VERSION 5.8 ;
BUSBITCHARS "[]" ;
DIVIDERCHAR "/" ;
UNITS
    DATABASE MICRONS 1000 ;
END UNITS

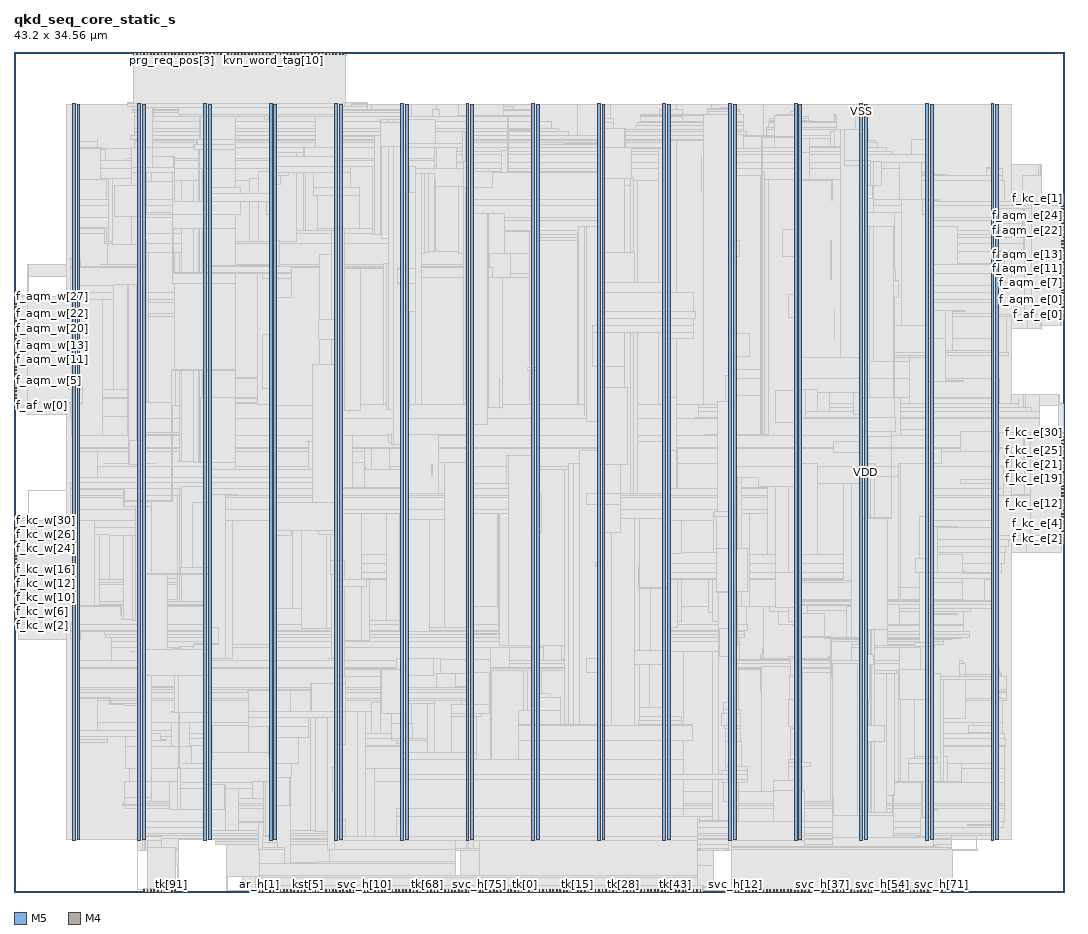
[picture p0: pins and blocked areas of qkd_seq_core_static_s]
MACRO qkd_seq_core_static_s
  FOREIGN qkd_seq_core_static_s 0 0 ;
  CLASS BLOCK ;
  SIZE 43.2 BY 34.56 ;
  PIN ar_h[0]
    DIRECTION INPUT ;
    USE SIGNAL ;
    PORT
      LAYER M5 ;
        RECT  9.936 0 9.96 0.084 ;
    END
  END ar_h[0]
  PIN ar_h[1]
    DIRECTION INPUT ;
    USE SIGNAL ;
    PORT
      LAYER M5 ;
        RECT  10.08 0 10.104 0.084 ;
    END
  END ar_h[1]
  PIN ar_h[2]
    DIRECTION INPUT ;
    USE SIGNAL ;
    PORT
      LAYER M5 ;
        RECT  10.224 0 10.248 0.084 ;
    END
  END ar_h[2]
  PIN ar_h[3]
    DIRECTION INPUT ;
    USE SIGNAL ;
    PORT
      LAYER M5 ;
        RECT  10.368 0 10.392 0.084 ;
    END
  END ar_h[3]
  PIN ar_h[4]
    DIRECTION INPUT ;
    USE SIGNAL ;
    PORT
      LAYER M5 ;
        RECT  10.512 0 10.536 0.084 ;
    END
  END ar_h[4]
  PIN ar_h[5]
    DIRECTION INPUT ;
    USE SIGNAL ;
    PORT
      LAYER M5 ;
        RECT  10.656 0 10.68 0.084 ;
    END
  END ar_h[5]
  PIN ar_h[6]
    DIRECTION INPUT ;
    USE SIGNAL ;
    PORT
      LAYER M5 ;
        RECT  10.8 0 10.824 0.084 ;
    END
  END ar_h[6]
  PIN ar_h[7]
    DIRECTION INPUT ;
    USE SIGNAL ;
    PORT
      LAYER M5 ;
        RECT  10.944 0 10.968 0.084 ;
    END
  END ar_h[7]
  PIN ck
    DIRECTION INPUT ;
    USE SIGNAL ;
    PORT
      LAYER M5 ;
        RECT  9.072 34.476 9.096 34.56 ;
    END
  END ck
  PIN f_af_e[0]
    DIRECTION INPUT ;
    USE SIGNAL ;
    PORT
      LAYER M4 ;
        RECT  43.116 23.76 43.2 23.784 ;
    END
  END f_af_e[0]
  PIN f_af_e[1]
    DIRECTION INPUT ;
    USE SIGNAL ;
    PORT
      LAYER M4 ;
        RECT  43.116 23.904 43.2 23.928 ;
    END
  END f_af_e[1]
  PIN f_af_w[0]
    DIRECTION INPUT ;
    USE SIGNAL ;
    PORT
      LAYER M4 ;
        RECT  0 20.016 0.084 20.04 ;
    END
  END f_af_w[0]
  PIN f_af_w[1]
    DIRECTION INPUT ;
    USE SIGNAL ;
    PORT
      LAYER M4 ;
        RECT  0 20.16 0.084 20.184 ;
    END
  END f_af_w[1]
  PIN f_aqm_e[0]
    DIRECTION OUTPUT ;
    USE SIGNAL ;
    PORT
      LAYER M4 ;
        RECT  43.116 24.048 43.2 24.072 ;
    END
  END f_aqm_e[0]
  PIN f_aqm_e[10]
    DIRECTION OUTPUT ;
    USE SIGNAL ;
    PORT
      LAYER M4 ;
        RECT  43.116 25.488 43.2 25.512 ;
    END
  END f_aqm_e[10]
  PIN f_aqm_e[11]
    DIRECTION OUTPUT ;
    USE SIGNAL ;
    PORT
      LAYER M4 ;
        RECT  43.116 25.632 43.2 25.656 ;
    END
  END f_aqm_e[11]
  PIN f_aqm_e[12]
    DIRECTION OUTPUT ;
    USE SIGNAL ;
    PORT
      LAYER M4 ;
        RECT  43.116 25.776 43.2 25.8 ;
    END
  END f_aqm_e[12]
  PIN f_aqm_e[13]
    DIRECTION OUTPUT ;
    USE SIGNAL ;
    PORT
      LAYER M4 ;
        RECT  43.116 25.92 43.2 25.944 ;
    END
  END f_aqm_e[13]
  PIN f_aqm_e[14]
    DIRECTION OUTPUT ;
    USE SIGNAL ;
    PORT
      LAYER M4 ;
        RECT  43.116 26.064 43.2 26.088 ;
    END
  END f_aqm_e[14]
  PIN f_aqm_e[15]
    DIRECTION OUTPUT ;
    USE SIGNAL ;
    PORT
      LAYER M4 ;
        RECT  43.116 26.208 43.2 26.232 ;
    END
  END f_aqm_e[15]
  PIN f_aqm_e[16]
    DIRECTION OUTPUT ;
    USE SIGNAL ;
    PORT
      LAYER M4 ;
        RECT  43.116 26.352 43.2 26.376 ;
    END
  END f_aqm_e[16]
  PIN f_aqm_e[17]
    DIRECTION OUTPUT ;
    USE SIGNAL ;
    PORT
      LAYER M4 ;
        RECT  43.116 26.496 43.2 26.52 ;
    END
  END f_aqm_e[17]
  PIN f_aqm_e[18]
    DIRECTION OUTPUT ;
    USE SIGNAL ;
    PORT
      LAYER M4 ;
        RECT  43.116 26.64 43.2 26.664 ;
    END
  END f_aqm_e[18]
  PIN f_aqm_e[19]
    DIRECTION OUTPUT ;
    USE SIGNAL ;
    PORT
      LAYER M4 ;
        RECT  43.116 26.784 43.2 26.808 ;
    END
  END f_aqm_e[19]
  PIN f_aqm_e[1]
    DIRECTION OUTPUT ;
    USE SIGNAL ;
    PORT
      LAYER M4 ;
        RECT  43.116 24.192 43.2 24.216 ;
    END
  END f_aqm_e[1]
  PIN f_aqm_e[20]
    DIRECTION OUTPUT ;
    USE SIGNAL ;
    PORT
      LAYER M4 ;
        RECT  43.116 26.928 43.2 26.952 ;
    END
  END f_aqm_e[20]
  PIN f_aqm_e[21]
    DIRECTION OUTPUT ;
    USE SIGNAL ;
    PORT
      LAYER M4 ;
        RECT  43.116 27.072 43.2 27.096 ;
    END
  END f_aqm_e[21]
  PIN f_aqm_e[22]
    DIRECTION OUTPUT ;
    USE SIGNAL ;
    PORT
      LAYER M4 ;
        RECT  43.116 27.216 43.2 27.24 ;
    END
  END f_aqm_e[22]
  PIN f_aqm_e[23]
    DIRECTION OUTPUT ;
    USE SIGNAL ;
    PORT
      LAYER M4 ;
        RECT  43.116 27.36 43.2 27.384 ;
    END
  END f_aqm_e[23]
  PIN f_aqm_e[24]
    DIRECTION OUTPUT ;
    USE SIGNAL ;
    PORT
      LAYER M4 ;
        RECT  43.116 27.504 43.2 27.528 ;
    END
  END f_aqm_e[24]
  PIN f_aqm_e[25]
    DIRECTION OUTPUT ;
    USE SIGNAL ;
    PORT
      LAYER M4 ;
        RECT  43.116 27.648 43.2 27.672 ;
    END
  END f_aqm_e[25]
  PIN f_aqm_e[26]
    DIRECTION OUTPUT ;
    USE SIGNAL ;
    PORT
      LAYER M4 ;
        RECT  43.116 27.792 43.2 27.816 ;
    END
  END f_aqm_e[26]
  PIN f_aqm_e[27]
    DIRECTION OUTPUT ;
    USE SIGNAL ;
    PORT
      LAYER M4 ;
        RECT  43.116 27.936 43.2 27.96 ;
    END
  END f_aqm_e[27]
  PIN f_aqm_e[2]
    DIRECTION OUTPUT ;
    USE SIGNAL ;
    PORT
      LAYER M4 ;
        RECT  43.116 24.336 43.2 24.36 ;
    END
  END f_aqm_e[2]
  PIN f_aqm_e[3]
    DIRECTION OUTPUT ;
    USE SIGNAL ;
    PORT
      LAYER M4 ;
        RECT  43.116 24.48 43.2 24.504 ;
    END
  END f_aqm_e[3]
  PIN f_aqm_e[4]
    DIRECTION OUTPUT ;
    USE SIGNAL ;
    PORT
      LAYER M4 ;
        RECT  43.116 24.624 43.2 24.648 ;
    END
  END f_aqm_e[4]
  PIN f_aqm_e[5]
    DIRECTION OUTPUT ;
    USE SIGNAL ;
    PORT
      LAYER M4 ;
        RECT  43.116 24.768 43.2 24.792 ;
    END
  END f_aqm_e[5]
  PIN f_aqm_e[6]
    DIRECTION OUTPUT ;
    USE SIGNAL ;
    PORT
      LAYER M4 ;
        RECT  43.116 24.912 43.2 24.936 ;
    END
  END f_aqm_e[6]
  PIN f_aqm_e[7]
    DIRECTION OUTPUT ;
    USE SIGNAL ;
    PORT
      LAYER M4 ;
        RECT  43.116 25.056 43.2 25.08 ;
    END
  END f_aqm_e[7]
  PIN f_aqm_e[8]
    DIRECTION OUTPUT ;
    USE SIGNAL ;
    PORT
      LAYER M4 ;
        RECT  43.116 25.2 43.2 25.224 ;
    END
  END f_aqm_e[8]
  PIN f_aqm_e[9]
    DIRECTION OUTPUT ;
    USE SIGNAL ;
    PORT
      LAYER M4 ;
        RECT  43.116 25.344 43.2 25.368 ;
    END
  END f_aqm_e[9]
  PIN f_aqm_w[0]
    DIRECTION OUTPUT ;
    USE SIGNAL ;
    PORT
      LAYER M4 ;
        RECT  0 20.304 0.084 20.328 ;
    END
  END f_aqm_w[0]
  PIN f_aqm_w[10]
    DIRECTION OUTPUT ;
    USE SIGNAL ;
    PORT
      LAYER M4 ;
        RECT  0 21.744 0.084 21.768 ;
    END
  END f_aqm_w[10]
  PIN f_aqm_w[11]
    DIRECTION OUTPUT ;
    USE SIGNAL ;
    PORT
      LAYER M4 ;
        RECT  0 21.888 0.084 21.912 ;
    END
  END f_aqm_w[11]
  PIN f_aqm_w[12]
    DIRECTION OUTPUT ;
    USE SIGNAL ;
    PORT
      LAYER M4 ;
        RECT  0 22.032 0.084 22.056 ;
    END
  END f_aqm_w[12]
  PIN f_aqm_w[13]
    DIRECTION OUTPUT ;
    USE SIGNAL ;
    PORT
      LAYER M4 ;
        RECT  0 22.176 0.084 22.2 ;
    END
  END f_aqm_w[13]
  PIN f_aqm_w[14]
    DIRECTION OUTPUT ;
    USE SIGNAL ;
    PORT
      LAYER M4 ;
        RECT  0 22.32 0.084 22.344 ;
    END
  END f_aqm_w[14]
  PIN f_aqm_w[15]
    DIRECTION OUTPUT ;
    USE SIGNAL ;
    PORT
      LAYER M4 ;
        RECT  0 22.464 0.084 22.488 ;
    END
  END f_aqm_w[15]
  PIN f_aqm_w[16]
    DIRECTION OUTPUT ;
    USE SIGNAL ;
    PORT
      LAYER M4 ;
        RECT  0 22.608 0.084 22.632 ;
    END
  END f_aqm_w[16]
  PIN f_aqm_w[17]
    DIRECTION OUTPUT ;
    USE SIGNAL ;
    PORT
      LAYER M4 ;
        RECT  0 22.752 0.084 22.776 ;
    END
  END f_aqm_w[17]
  PIN f_aqm_w[18]
    DIRECTION OUTPUT ;
    USE SIGNAL ;
    PORT
      LAYER M4 ;
        RECT  0 22.896 0.084 22.92 ;
    END
  END f_aqm_w[18]
  PIN f_aqm_w[19]
    DIRECTION OUTPUT ;
    USE SIGNAL ;
    PORT
      LAYER M4 ;
        RECT  0 23.04 0.084 23.064 ;
    END
  END f_aqm_w[19]
  PIN f_aqm_w[1]
    DIRECTION OUTPUT ;
    USE SIGNAL ;
    PORT
      LAYER M4 ;
        RECT  0 20.448 0.084 20.472 ;
    END
  END f_aqm_w[1]
  PIN f_aqm_w[20]
    DIRECTION OUTPUT ;
    USE SIGNAL ;
    PORT
      LAYER M4 ;
        RECT  0 23.184 0.084 23.208 ;
    END
  END f_aqm_w[20]
  PIN f_aqm_w[21]
    DIRECTION OUTPUT ;
    USE SIGNAL ;
    PORT
      LAYER M4 ;
        RECT  0 23.328 0.084 23.352 ;
    END
  END f_aqm_w[21]
  PIN f_aqm_w[22]
    DIRECTION OUTPUT ;
    USE SIGNAL ;
    PORT
      LAYER M4 ;
        RECT  0 23.472 0.084 23.496 ;
    END
  END f_aqm_w[22]
  PIN f_aqm_w[23]
    DIRECTION OUTPUT ;
    USE SIGNAL ;
    PORT
      LAYER M4 ;
        RECT  0 23.616 0.084 23.64 ;
    END
  END f_aqm_w[23]
  PIN f_aqm_w[24]
    DIRECTION OUTPUT ;
    USE SIGNAL ;
    PORT
      LAYER M4 ;
        RECT  0 23.76 0.084 23.784 ;
    END
  END f_aqm_w[24]
  PIN f_aqm_w[25]
    DIRECTION OUTPUT ;
    USE SIGNAL ;
    PORT
      LAYER M4 ;
        RECT  0 23.904 0.084 23.928 ;
    END
  END f_aqm_w[25]
  PIN f_aqm_w[26]
    DIRECTION OUTPUT ;
    USE SIGNAL ;
    PORT
      LAYER M4 ;
        RECT  0 24.048 0.084 24.072 ;
    END
  END f_aqm_w[26]
  PIN f_aqm_w[27]
    DIRECTION OUTPUT ;
    USE SIGNAL ;
    PORT
      LAYER M4 ;
        RECT  0 24.192 0.084 24.216 ;
    END
  END f_aqm_w[27]
  PIN f_aqm_w[2]
    DIRECTION OUTPUT ;
    USE SIGNAL ;
    PORT
      LAYER M4 ;
        RECT  0 20.592 0.084 20.616 ;
    END
  END f_aqm_w[2]
  PIN f_aqm_w[3]
    DIRECTION OUTPUT ;
    USE SIGNAL ;
    PORT
      LAYER M4 ;
        RECT  0 20.736 0.084 20.76 ;
    END
  END f_aqm_w[3]
  PIN f_aqm_w[4]
    DIRECTION OUTPUT ;
    USE SIGNAL ;
    PORT
      LAYER M4 ;
        RECT  0 20.88 0.084 20.904 ;
    END
  END f_aqm_w[4]
  PIN f_aqm_w[5]
    DIRECTION OUTPUT ;
    USE SIGNAL ;
    PORT
      LAYER M4 ;
        RECT  0 21.024 0.084 21.048 ;
    END
  END f_aqm_w[5]
  PIN f_aqm_w[6]
    DIRECTION OUTPUT ;
    USE SIGNAL ;
    PORT
      LAYER M4 ;
        RECT  0 21.168 0.084 21.192 ;
    END
  END f_aqm_w[6]
  PIN f_aqm_w[7]
    DIRECTION OUTPUT ;
    USE SIGNAL ;
    PORT
      LAYER M4 ;
        RECT  0 21.312 0.084 21.336 ;
    END
  END f_aqm_w[7]
  PIN f_aqm_w[8]
    DIRECTION OUTPUT ;
    USE SIGNAL ;
    PORT
      LAYER M4 ;
        RECT  0 21.456 0.084 21.48 ;
    END
  END f_aqm_w[8]
  PIN f_aqm_w[9]
    DIRECTION OUTPUT ;
    USE SIGNAL ;
    PORT
      LAYER M4 ;
        RECT  0 21.6 0.084 21.624 ;
    END
  END f_aqm_w[9]
  PIN f_kc_e[0]
    DIRECTION OUTPUT ;
    USE SIGNAL ;
    PORT
      LAYER M4 ;
        RECT  43.116 28.08 43.2 28.104 ;
    END
  END f_kc_e[0]
  PIN f_kc_e[10]
    DIRECTION OUTPUT ;
    USE SIGNAL ;
    PORT
      LAYER M4 ;
        RECT  43.116 15.696 43.2 15.72 ;
    END
  END f_kc_e[10]
  PIN f_kc_e[11]
    DIRECTION OUTPUT ;
    USE SIGNAL ;
    PORT
      LAYER M4 ;
        RECT  43.116 15.84 43.2 15.864 ;
    END
  END f_kc_e[11]
  PIN f_kc_e[12]
    DIRECTION OUTPUT ;
    USE SIGNAL ;
    PORT
      LAYER M4 ;
        RECT  43.116 15.984 43.2 16.008 ;
    END
  END f_kc_e[12]
  PIN f_kc_e[13]
    DIRECTION OUTPUT ;
    USE SIGNAL ;
    PORT
      LAYER M4 ;
        RECT  43.116 16.128 43.2 16.152 ;
    END
  END f_kc_e[13]
  PIN f_kc_e[14]
    DIRECTION OUTPUT ;
    USE SIGNAL ;
    PORT
      LAYER M4 ;
        RECT  43.116 16.272 43.2 16.296 ;
    END
  END f_kc_e[14]
  PIN f_kc_e[15]
    DIRECTION OUTPUT ;
    USE SIGNAL ;
    PORT
      LAYER M4 ;
        RECT  43.116 16.416 43.2 16.44 ;
    END
  END f_kc_e[15]
  PIN f_kc_e[16]
    DIRECTION OUTPUT ;
    USE SIGNAL ;
    PORT
      LAYER M4 ;
        RECT  43.116 16.56 43.2 16.584 ;
    END
  END f_kc_e[16]
  PIN f_kc_e[17]
    DIRECTION OUTPUT ;
    USE SIGNAL ;
    PORT
      LAYER M4 ;
        RECT  43.116 16.704 43.2 16.728 ;
    END
  END f_kc_e[17]
  PIN f_kc_e[18]
    DIRECTION OUTPUT ;
    USE SIGNAL ;
    PORT
      LAYER M4 ;
        RECT  43.116 16.848 43.2 16.872 ;
    END
  END f_kc_e[18]
  PIN f_kc_e[19]
    DIRECTION OUTPUT ;
    USE SIGNAL ;
    PORT
      LAYER M4 ;
        RECT  43.116 16.992 43.2 17.016 ;
    END
  END f_kc_e[19]
  PIN f_kc_e[1]
    DIRECTION OUTPUT ;
    USE SIGNAL ;
    PORT
      LAYER M4 ;
        RECT  43.116 28.224 43.2 28.248 ;
    END
  END f_kc_e[1]
  PIN f_kc_e[20]
    DIRECTION OUTPUT ;
    USE SIGNAL ;
    PORT
      LAYER M4 ;
        RECT  43.116 17.136 43.2 17.16 ;
    END
  END f_kc_e[20]
  PIN f_kc_e[21]
    DIRECTION OUTPUT ;
    USE SIGNAL ;
    PORT
      LAYER M4 ;
        RECT  43.116 17.28 43.2 17.304 ;
    END
  END f_kc_e[21]
  PIN f_kc_e[22]
    DIRECTION OUTPUT ;
    USE SIGNAL ;
    PORT
      LAYER M4 ;
        RECT  43.116 17.424 43.2 17.448 ;
    END
  END f_kc_e[22]
  PIN f_kc_e[23]
    DIRECTION OUTPUT ;
    USE SIGNAL ;
    PORT
      LAYER M4 ;
        RECT  43.116 17.568 43.2 17.592 ;
    END
  END f_kc_e[23]
  PIN f_kc_e[24]
    DIRECTION OUTPUT ;
    USE SIGNAL ;
    PORT
      LAYER M4 ;
        RECT  43.116 17.712 43.2 17.736 ;
    END
  END f_kc_e[24]
  PIN f_kc_e[25]
    DIRECTION OUTPUT ;
    USE SIGNAL ;
    PORT
      LAYER M4 ;
        RECT  43.116 17.856 43.2 17.88 ;
    END
  END f_kc_e[25]
  PIN f_kc_e[26]
    DIRECTION OUTPUT ;
    USE SIGNAL ;
    PORT
      LAYER M4 ;
        RECT  43.116 18 43.2 18.024 ;
    END
  END f_kc_e[26]
  PIN f_kc_e[27]
    DIRECTION OUTPUT ;
    USE SIGNAL ;
    PORT
      LAYER M4 ;
        RECT  43.116 18.144 43.2 18.168 ;
    END
  END f_kc_e[27]
  PIN f_kc_e[28]
    DIRECTION OUTPUT ;
    USE SIGNAL ;
    PORT
      LAYER M4 ;
        RECT  43.116 18.288 43.2 18.312 ;
    END
  END f_kc_e[28]
  PIN f_kc_e[29]
    DIRECTION OUTPUT ;
    USE SIGNAL ;
    PORT
      LAYER M4 ;
        RECT  43.116 18.432 43.2 18.456 ;
    END
  END f_kc_e[29]
  PIN f_kc_e[2]
    DIRECTION OUTPUT ;
    USE SIGNAL ;
    PORT
      LAYER M4 ;
        RECT  43.116 14.544 43.2 14.568 ;
    END
  END f_kc_e[2]
  PIN f_kc_e[30]
    DIRECTION OUTPUT ;
    USE SIGNAL ;
    PORT
      LAYER M4 ;
        RECT  43.116 18.576 43.2 18.6 ;
    END
  END f_kc_e[30]
  PIN f_kc_e[31]
    DIRECTION OUTPUT ;
    USE SIGNAL ;
    PORT
      LAYER M4 ;
        RECT  43.116 18.72 43.2 18.744 ;
    END
  END f_kc_e[31]
  PIN f_kc_e[32]
    DIRECTION OUTPUT ;
    USE SIGNAL ;
    PORT
      LAYER M4 ;
        RECT  43.116 18.864 43.2 18.888 ;
    END
  END f_kc_e[32]
  PIN f_kc_e[3]
    DIRECTION OUTPUT ;
    USE SIGNAL ;
    PORT
      LAYER M4 ;
        RECT  43.116 14.688 43.2 14.712 ;
    END
  END f_kc_e[3]
  PIN f_kc_e[4]
    DIRECTION OUTPUT ;
    USE SIGNAL ;
    PORT
      LAYER M4 ;
        RECT  43.116 14.832 43.2 14.856 ;
    END
  END f_kc_e[4]
  PIN f_kc_e[5]
    DIRECTION OUTPUT ;
    USE SIGNAL ;
    PORT
      LAYER M4 ;
        RECT  43.116 14.976 43.2 15 ;
    END
  END f_kc_e[5]
  PIN f_kc_e[6]
    DIRECTION OUTPUT ;
    USE SIGNAL ;
    PORT
      LAYER M4 ;
        RECT  43.116 15.12 43.2 15.144 ;
    END
  END f_kc_e[6]
  PIN f_kc_e[7]
    DIRECTION OUTPUT ;
    USE SIGNAL ;
    PORT
      LAYER M4 ;
        RECT  43.116 15.264 43.2 15.288 ;
    END
  END f_kc_e[7]
  PIN f_kc_e[8]
    DIRECTION OUTPUT ;
    USE SIGNAL ;
    PORT
      LAYER M4 ;
        RECT  43.116 15.408 43.2 15.432 ;
    END
  END f_kc_e[8]
  PIN f_kc_e[9]
    DIRECTION OUTPUT ;
    USE SIGNAL ;
    PORT
      LAYER M4 ;
        RECT  43.116 15.552 43.2 15.576 ;
    END
  END f_kc_e[9]
  PIN f_kc_w[0]
    DIRECTION OUTPUT ;
    USE SIGNAL ;
    PORT
      LAYER M4 ;
        RECT  0 24.336 0.084 24.36 ;
    END
  END f_kc_w[0]
  PIN f_kc_w[10]
    DIRECTION OUTPUT ;
    USE SIGNAL ;
    PORT
      LAYER M4 ;
        RECT  0 12.096 0.084 12.12 ;
    END
  END f_kc_w[10]
  PIN f_kc_w[11]
    DIRECTION OUTPUT ;
    USE SIGNAL ;
    PORT
      LAYER M4 ;
        RECT  0 12.24 0.084 12.264 ;
    END
  END f_kc_w[11]
  PIN f_kc_w[12]
    DIRECTION OUTPUT ;
    USE SIGNAL ;
    PORT
      LAYER M4 ;
        RECT  0 12.384 0.084 12.408 ;
    END
  END f_kc_w[12]
  PIN f_kc_w[13]
    DIRECTION OUTPUT ;
    USE SIGNAL ;
    PORT
      LAYER M4 ;
        RECT  0 12.528 0.084 12.552 ;
    END
  END f_kc_w[13]
  PIN f_kc_w[14]
    DIRECTION OUTPUT ;
    USE SIGNAL ;
    PORT
      LAYER M4 ;
        RECT  0 12.672 0.084 12.696 ;
    END
  END f_kc_w[14]
  PIN f_kc_w[15]
    DIRECTION OUTPUT ;
    USE SIGNAL ;
    PORT
      LAYER M4 ;
        RECT  0 12.816 0.084 12.84 ;
    END
  END f_kc_w[15]
  PIN f_kc_w[16]
    DIRECTION OUTPUT ;
    USE SIGNAL ;
    PORT
      LAYER M4 ;
        RECT  0 12.96 0.084 12.984 ;
    END
  END f_kc_w[16]
  PIN f_kc_w[17]
    DIRECTION OUTPUT ;
    USE SIGNAL ;
    PORT
      LAYER M4 ;
        RECT  0 13.104 0.084 13.128 ;
    END
  END f_kc_w[17]
  PIN f_kc_w[18]
    DIRECTION OUTPUT ;
    USE SIGNAL ;
    PORT
      LAYER M4 ;
        RECT  0 13.248 0.084 13.272 ;
    END
  END f_kc_w[18]
  PIN f_kc_w[19]
    DIRECTION OUTPUT ;
    USE SIGNAL ;
    PORT
      LAYER M4 ;
        RECT  0 13.392 0.084 13.416 ;
    END
  END f_kc_w[19]
  PIN f_kc_w[1]
    DIRECTION OUTPUT ;
    USE SIGNAL ;
    PORT
      LAYER M4 ;
        RECT  0 24.48 0.084 24.504 ;
    END
  END f_kc_w[1]
  PIN f_kc_w[20]
    DIRECTION OUTPUT ;
    USE SIGNAL ;
    PORT
      LAYER M4 ;
        RECT  0 13.536 0.084 13.56 ;
    END
  END f_kc_w[20]
  PIN f_kc_w[21]
    DIRECTION OUTPUT ;
    USE SIGNAL ;
    PORT
      LAYER M4 ;
        RECT  0 13.68 0.084 13.704 ;
    END
  END f_kc_w[21]
  PIN f_kc_w[22]
    DIRECTION OUTPUT ;
    USE SIGNAL ;
    PORT
      LAYER M4 ;
        RECT  0 13.824 0.084 13.848 ;
    END
  END f_kc_w[22]
  PIN f_kc_w[23]
    DIRECTION OUTPUT ;
    USE SIGNAL ;
    PORT
      LAYER M4 ;
        RECT  0 13.968 0.084 13.992 ;
    END
  END f_kc_w[23]
  PIN f_kc_w[24]
    DIRECTION OUTPUT ;
    USE SIGNAL ;
    PORT
      LAYER M4 ;
        RECT  0 14.112 0.084 14.136 ;
    END
  END f_kc_w[24]
  PIN f_kc_w[25]
    DIRECTION OUTPUT ;
    USE SIGNAL ;
    PORT
      LAYER M4 ;
        RECT  0 14.256 0.084 14.28 ;
    END
  END f_kc_w[25]
  PIN f_kc_w[26]
    DIRECTION OUTPUT ;
    USE SIGNAL ;
    PORT
      LAYER M4 ;
        RECT  0 14.4 0.084 14.424 ;
    END
  END f_kc_w[26]
  PIN f_kc_w[27]
    DIRECTION OUTPUT ;
    USE SIGNAL ;
    PORT
      LAYER M4 ;
        RECT  0 14.544 0.084 14.568 ;
    END
  END f_kc_w[27]
  PIN f_kc_w[28]
    DIRECTION OUTPUT ;
    USE SIGNAL ;
    PORT
      LAYER M4 ;
        RECT  0 14.688 0.084 14.712 ;
    END
  END f_kc_w[28]
  PIN f_kc_w[29]
    DIRECTION OUTPUT ;
    USE SIGNAL ;
    PORT
      LAYER M4 ;
        RECT  0 14.832 0.084 14.856 ;
    END
  END f_kc_w[29]
  PIN f_kc_w[2]
    DIRECTION OUTPUT ;
    USE SIGNAL ;
    PORT
      LAYER M4 ;
        RECT  0 10.944 0.084 10.968 ;
    END
  END f_kc_w[2]
  PIN f_kc_w[30]
    DIRECTION OUTPUT ;
    USE SIGNAL ;
    PORT
      LAYER M4 ;
        RECT  0 14.976 0.084 15 ;
    END
  END f_kc_w[30]
  PIN f_kc_w[31]
    DIRECTION OUTPUT ;
    USE SIGNAL ;
    PORT
      LAYER M4 ;
        RECT  0 15.12 0.084 15.144 ;
    END
  END f_kc_w[31]
  PIN f_kc_w[32]
    DIRECTION OUTPUT ;
    USE SIGNAL ;
    PORT
      LAYER M4 ;
        RECT  0 15.264 0.084 15.288 ;
    END
  END f_kc_w[32]
  PIN f_kc_w[3]
    DIRECTION OUTPUT ;
    USE SIGNAL ;
    PORT
      LAYER M4 ;
        RECT  0 11.088 0.084 11.112 ;
    END
  END f_kc_w[3]
  PIN f_kc_w[4]
    DIRECTION OUTPUT ;
    USE SIGNAL ;
    PORT
      LAYER M4 ;
        RECT  0 11.232 0.084 11.256 ;
    END
  END f_kc_w[4]
  PIN f_kc_w[5]
    DIRECTION OUTPUT ;
    USE SIGNAL ;
    PORT
      LAYER M4 ;
        RECT  0 11.376 0.084 11.4 ;
    END
  END f_kc_w[5]
  PIN f_kc_w[6]
    DIRECTION OUTPUT ;
    USE SIGNAL ;
    PORT
      LAYER M4 ;
        RECT  0 11.52 0.084 11.544 ;
    END
  END f_kc_w[6]
  PIN f_kc_w[7]
    DIRECTION OUTPUT ;
    USE SIGNAL ;
    PORT
      LAYER M4 ;
        RECT  0 11.664 0.084 11.688 ;
    END
  END f_kc_w[7]
  PIN f_kc_w[8]
    DIRECTION OUTPUT ;
    USE SIGNAL ;
    PORT
      LAYER M4 ;
        RECT  0 11.808 0.084 11.832 ;
    END
  END f_kc_w[8]
  PIN f_kc_w[9]
    DIRECTION OUTPUT ;
    USE SIGNAL ;
    PORT
      LAYER M4 ;
        RECT  0 11.952 0.084 11.976 ;
    END
  END f_kc_w[9]
  PIN hf
    DIRECTION INPUT ;
    USE SIGNAL ;
    PORT
      LAYER M5 ;
        RECT  11.088 0 11.112 0.084 ;
    END
  END hf
  PIN hs
    DIRECTION OUTPUT ;
    USE SIGNAL ;
    PORT
      LAYER M5 ;
        RECT  11.232 0 11.256 0.084 ;
    END
  END hs
  PIN kst[0]
    DIRECTION OUTPUT ;
    USE SIGNAL ;
    PORT
      LAYER M5 ;
        RECT  11.376 0 11.4 0.084 ;
    END
  END kst[0]
  PIN kst[1]
    DIRECTION OUTPUT ;
    USE SIGNAL ;
    PORT
      LAYER M5 ;
        RECT  11.52 0 11.544 0.084 ;
    END
  END kst[1]
  PIN kst[2]
    DIRECTION OUTPUT ;
    USE SIGNAL ;
    PORT
      LAYER M5 ;
        RECT  11.664 0 11.688 0.084 ;
    END
  END kst[2]
  PIN kst[3]
    DIRECTION OUTPUT ;
    USE SIGNAL ;
    PORT
      LAYER M5 ;
        RECT  11.808 0 11.832 0.084 ;
    END
  END kst[3]
  PIN kst[4]
    DIRECTION OUTPUT ;
    USE SIGNAL ;
    PORT
      LAYER M5 ;
        RECT  11.952 0 11.976 0.084 ;
    END
  END kst[4]
  PIN kst[5]
    DIRECTION OUTPUT ;
    USE SIGNAL ;
    PORT
      LAYER M5 ;
        RECT  12.096 0 12.12 0.084 ;
    END
  END kst[5]
  PIN kst[6]
    DIRECTION OUTPUT ;
    USE SIGNAL ;
    PORT
      LAYER M5 ;
        RECT  12.24 0 12.264 0.084 ;
    END
  END kst[6]
  PIN kst[7]
    DIRECTION OUTPUT ;
    USE SIGNAL ;
    PORT
      LAYER M5 ;
        RECT  12.384 0 12.408 0.084 ;
    END
  END kst[7]
  PIN kst[8]
    DIRECTION OUTPUT ;
    USE SIGNAL ;
    PORT
      LAYER M5 ;
        RECT  12.528 0 12.552 0.084 ;
    END
  END kst[8]
  PIN kst[9]
    DIRECTION OUTPUT ;
    USE SIGNAL ;
    PORT
      LAYER M5 ;
        RECT  12.672 0 12.696 0.084 ;
    END
  END kst[9]
  PIN kvn_word_tag[0]
    DIRECTION INPUT ;
    USE SIGNAL ;
    PORT
      LAYER M5 ;
        RECT  9.216 34.476 9.24 34.56 ;
    END
  END kvn_word_tag[0]
  PIN kvn_word_tag[10]
    DIRECTION INPUT ;
    USE SIGNAL ;
    PORT
      LAYER M5 ;
        RECT  10.656 34.476 10.68 34.56 ;
    END
  END kvn_word_tag[10]
  PIN kvn_word_tag[1]
    DIRECTION INPUT ;
    USE SIGNAL ;
    PORT
      LAYER M5 ;
        RECT  9.36 34.476 9.384 34.56 ;
    END
  END kvn_word_tag[1]
  PIN kvn_word_tag[2]
    DIRECTION INPUT ;
    USE SIGNAL ;
    PORT
      LAYER M5 ;
        RECT  9.504 34.476 9.528 34.56 ;
    END
  END kvn_word_tag[2]
  PIN kvn_word_tag[3]
    DIRECTION INPUT ;
    USE SIGNAL ;
    PORT
      LAYER M5 ;
        RECT  9.648 34.476 9.672 34.56 ;
    END
  END kvn_word_tag[3]
  PIN kvn_word_tag[4]
    DIRECTION INPUT ;
    USE SIGNAL ;
    PORT
      LAYER M5 ;
        RECT  9.792 34.476 9.816 34.56 ;
    END
  END kvn_word_tag[4]
  PIN kvn_word_tag[5]
    DIRECTION INPUT ;
    USE SIGNAL ;
    PORT
      LAYER M5 ;
        RECT  9.936 34.476 9.96 34.56 ;
    END
  END kvn_word_tag[5]
  PIN kvn_word_tag[6]
    DIRECTION INPUT ;
    USE SIGNAL ;
    PORT
      LAYER M5 ;
        RECT  10.08 34.476 10.104 34.56 ;
    END
  END kvn_word_tag[6]
  PIN kvn_word_tag[7]
    DIRECTION INPUT ;
    USE SIGNAL ;
    PORT
      LAYER M5 ;
        RECT  10.224 34.476 10.248 34.56 ;
    END
  END kvn_word_tag[7]
  PIN kvn_word_tag[8]
    DIRECTION INPUT ;
    USE SIGNAL ;
    PORT
      LAYER M5 ;
        RECT  10.368 34.476 10.392 34.56 ;
    END
  END kvn_word_tag[8]
  PIN kvn_word_tag[9]
    DIRECTION INPUT ;
    USE SIGNAL ;
    PORT
      LAYER M5 ;
        RECT  10.512 34.476 10.536 34.56 ;
    END
  END kvn_word_tag[9]
  PIN kvn_word_valid
    DIRECTION INPUT ;
    USE SIGNAL ;
    PORT
      LAYER M5 ;
        RECT  10.8 34.476 10.824 34.56 ;
    END
  END kvn_word_valid
  PIN lp_ctx_t[0]
    DIRECTION INPUT ;
    USE SIGNAL ;
    PORT
      LAYER M5 ;
        RECT  10.944 34.476 10.968 34.56 ;
    END
  END lp_ctx_t[0]
  PIN lp_ctx_t[10]
    DIRECTION INPUT ;
    USE SIGNAL ;
    PORT
      LAYER M5 ;
        RECT  12.384 34.476 12.408 34.56 ;
    END
  END lp_ctx_t[10]
  PIN lp_ctx_t[11]
    DIRECTION INPUT ;
    USE SIGNAL ;
    PORT
      LAYER M5 ;
        RECT  12.528 34.476 12.552 34.56 ;
    END
  END lp_ctx_t[11]
  PIN lp_ctx_t[12]
    DIRECTION INPUT ;
    USE SIGNAL ;
    PORT
      LAYER M5 ;
        RECT  12.672 34.476 12.696 34.56 ;
    END
  END lp_ctx_t[12]
  PIN lp_ctx_t[13]
    DIRECTION INPUT ;
    USE SIGNAL ;
    PORT
      LAYER M5 ;
        RECT  12.816 34.476 12.84 34.56 ;
    END
  END lp_ctx_t[13]
  PIN lp_ctx_t[1]
    DIRECTION INPUT ;
    USE SIGNAL ;
    PORT
      LAYER M5 ;
        RECT  11.088 34.476 11.112 34.56 ;
    END
  END lp_ctx_t[1]
  PIN lp_ctx_t[2]
    DIRECTION INPUT ;
    USE SIGNAL ;
    PORT
      LAYER M5 ;
        RECT  11.232 34.476 11.256 34.56 ;
    END
  END lp_ctx_t[2]
  PIN lp_ctx_t[3]
    DIRECTION INPUT ;
    USE SIGNAL ;
    PORT
      LAYER M5 ;
        RECT  11.376 34.476 11.4 34.56 ;
    END
  END lp_ctx_t[3]
  PIN lp_ctx_t[4]
    DIRECTION INPUT ;
    USE SIGNAL ;
    PORT
      LAYER M5 ;
        RECT  11.52 34.476 11.544 34.56 ;
    END
  END lp_ctx_t[4]
  PIN lp_ctx_t[5]
    DIRECTION INPUT ;
    USE SIGNAL ;
    PORT
      LAYER M5 ;
        RECT  11.664 34.476 11.688 34.56 ;
    END
  END lp_ctx_t[5]
  PIN lp_ctx_t[6]
    DIRECTION INPUT ;
    USE SIGNAL ;
    PORT
      LAYER M5 ;
        RECT  11.808 34.476 11.832 34.56 ;
    END
  END lp_ctx_t[6]
  PIN lp_ctx_t[7]
    DIRECTION INPUT ;
    USE SIGNAL ;
    PORT
      LAYER M5 ;
        RECT  11.952 34.476 11.976 34.56 ;
    END
  END lp_ctx_t[7]
  PIN lp_ctx_t[8]
    DIRECTION INPUT ;
    USE SIGNAL ;
    PORT
      LAYER M5 ;
        RECT  12.096 34.476 12.12 34.56 ;
    END
  END lp_ctx_t[8]
  PIN lp_ctx_t[9]
    DIRECTION INPUT ;
    USE SIGNAL ;
    PORT
      LAYER M5 ;
        RECT  12.24 34.476 12.264 34.56 ;
    END
  END lp_ctx_t[9]
  PIN lp_layer[0]
    DIRECTION INPUT ;
    USE SIGNAL ;
    PORT
      LAYER M5 ;
        RECT  12.96 34.476 12.984 34.56 ;
    END
  END lp_layer[0]
  PIN lp_layer[1]
    DIRECTION INPUT ;
    USE SIGNAL ;
    PORT
      LAYER M5 ;
        RECT  13.104 34.476 13.128 34.56 ;
    END
  END lp_layer[1]
  PIN lp_layer[2]
    DIRECTION INPUT ;
    USE SIGNAL ;
    PORT
      LAYER M5 ;
        RECT  13.248 34.476 13.272 34.56 ;
    END
  END lp_layer[2]
  PIN lp_layer[3]
    DIRECTION INPUT ;
    USE SIGNAL ;
    PORT
      LAYER M5 ;
        RECT  13.392 34.476 13.416 34.56 ;
    END
  END lp_layer[3]
  PIN lp_layer[4]
    DIRECTION INPUT ;
    USE SIGNAL ;
    PORT
      LAYER M5 ;
        RECT  13.536 34.476 13.56 34.56 ;
    END
  END lp_layer[4]
  PIN lp_layer[5]
    DIRECTION INPUT ;
    USE SIGNAL ;
    PORT
      LAYER M5 ;
        RECT  4.896 34.476 4.92 34.56 ;
    END
  END lp_layer[5]
  PIN lp_run
    DIRECTION INPUT ;
    USE SIGNAL ;
    PORT
      LAYER M5 ;
        RECT  5.04 34.476 5.064 34.56 ;
    END
  END lp_run
  PIN prg_q_beat[0]
    DIRECTION INPUT ;
    USE SIGNAL ;
    PORT
      LAYER M5 ;
        RECT  5.184 34.476 5.208 34.56 ;
    END
  END prg_q_beat[0]
  PIN prg_q_beat[1]
    DIRECTION INPUT ;
    USE SIGNAL ;
    PORT
      LAYER M5 ;
        RECT  5.328 34.476 5.352 34.56 ;
    END
  END prg_q_beat[1]
  PIN prg_q_beat[2]
    DIRECTION INPUT ;
    USE SIGNAL ;
    PORT
      LAYER M5 ;
        RECT  5.472 34.476 5.496 34.56 ;
    END
  END prg_q_beat[2]
  PIN prg_q_beat[3]
    DIRECTION INPUT ;
    USE SIGNAL ;
    PORT
      LAYER M5 ;
        RECT  5.616 34.476 5.64 34.56 ;
    END
  END prg_q_beat[3]
  PIN prg_q_beat[4]
    DIRECTION INPUT ;
    USE SIGNAL ;
    PORT
      LAYER M5 ;
        RECT  5.76 34.476 5.784 34.56 ;
    END
  END prg_q_beat[4]
  PIN prg_q_v
    DIRECTION INPUT ;
    USE SIGNAL ;
    PORT
      LAYER M5 ;
        RECT  5.904 34.476 5.928 34.56 ;
    END
  END prg_q_v
  PIN prg_req_pos[0]
    DIRECTION INPUT ;
    USE SIGNAL ;
    PORT
      LAYER M5 ;
        RECT  6.048 34.476 6.072 34.56 ;
    END
  END prg_req_pos[0]
  PIN prg_req_pos[10]
    DIRECTION INPUT ;
    USE SIGNAL ;
    PORT
      LAYER M5 ;
        RECT  7.488 34.476 7.512 34.56 ;
    END
  END prg_req_pos[10]
  PIN prg_req_pos[11]
    DIRECTION INPUT ;
    USE SIGNAL ;
    PORT
      LAYER M5 ;
        RECT  7.632 34.476 7.656 34.56 ;
    END
  END prg_req_pos[11]
  PIN prg_req_pos[12]
    DIRECTION INPUT ;
    USE SIGNAL ;
    PORT
      LAYER M5 ;
        RECT  7.776 34.476 7.8 34.56 ;
    END
  END prg_req_pos[12]
  PIN prg_req_pos[13]
    DIRECTION INPUT ;
    USE SIGNAL ;
    PORT
      LAYER M5 ;
        RECT  7.92 34.476 7.944 34.56 ;
    END
  END prg_req_pos[13]
  PIN prg_req_pos[14]
    DIRECTION INPUT ;
    USE SIGNAL ;
    PORT
      LAYER M5 ;
        RECT  8.064 34.476 8.088 34.56 ;
    END
  END prg_req_pos[14]
  PIN prg_req_pos[15]
    DIRECTION INPUT ;
    USE SIGNAL ;
    PORT
      LAYER M5 ;
        RECT  8.208 34.476 8.232 34.56 ;
    END
  END prg_req_pos[15]
  PIN prg_req_pos[16]
    DIRECTION INPUT ;
    USE SIGNAL ;
    PORT
      LAYER M5 ;
        RECT  8.352 34.476 8.376 34.56 ;
    END
  END prg_req_pos[16]
  PIN prg_req_pos[17]
    DIRECTION INPUT ;
    USE SIGNAL ;
    PORT
      LAYER M5 ;
        RECT  8.496 34.476 8.52 34.56 ;
    END
  END prg_req_pos[17]
  PIN prg_req_pos[1]
    DIRECTION INPUT ;
    USE SIGNAL ;
    PORT
      LAYER M5 ;
        RECT  6.192 34.476 6.216 34.56 ;
    END
  END prg_req_pos[1]
  PIN prg_req_pos[2]
    DIRECTION INPUT ;
    USE SIGNAL ;
    PORT
      LAYER M5 ;
        RECT  6.336 34.476 6.36 34.56 ;
    END
  END prg_req_pos[2]
  PIN prg_req_pos[3]
    DIRECTION INPUT ;
    USE SIGNAL ;
    PORT
      LAYER M5 ;
        RECT  6.48 34.476 6.504 34.56 ;
    END
  END prg_req_pos[3]
  PIN prg_req_pos[4]
    DIRECTION INPUT ;
    USE SIGNAL ;
    PORT
      LAYER M5 ;
        RECT  6.624 34.476 6.648 34.56 ;
    END
  END prg_req_pos[4]
  PIN prg_req_pos[5]
    DIRECTION INPUT ;
    USE SIGNAL ;
    PORT
      LAYER M5 ;
        RECT  6.768 34.476 6.792 34.56 ;
    END
  END prg_req_pos[5]
  PIN prg_req_pos[6]
    DIRECTION INPUT ;
    USE SIGNAL ;
    PORT
      LAYER M5 ;
        RECT  6.912 34.476 6.936 34.56 ;
    END
  END prg_req_pos[6]
  PIN prg_req_pos[7]
    DIRECTION INPUT ;
    USE SIGNAL ;
    PORT
      LAYER M5 ;
        RECT  7.056 34.476 7.08 34.56 ;
    END
  END prg_req_pos[7]
  PIN prg_req_pos[8]
    DIRECTION INPUT ;
    USE SIGNAL ;
    PORT
      LAYER M5 ;
        RECT  7.2 34.476 7.224 34.56 ;
    END
  END prg_req_pos[8]
  PIN prg_req_pos[9]
    DIRECTION INPUT ;
    USE SIGNAL ;
    PORT
      LAYER M5 ;
        RECT  7.344 34.476 7.368 34.56 ;
    END
  END prg_req_pos[9]
  PIN prg_req_v
    DIRECTION INPUT ;
    USE SIGNAL ;
    PORT
      LAYER M5 ;
        RECT  8.64 34.476 8.664 34.56 ;
    END
  END prg_req_v
  PIN rst_n
    DIRECTION INPUT ;
    USE SIGNAL ;
    PORT
      LAYER M5 ;
        RECT  12.816 0 12.84 0.084 ;
    END
  END rst_n
  PIN s_qpop
    DIRECTION OUTPUT ;
    USE SIGNAL ;
    PORT
      LAYER M5 ;
        RECT  8.784 34.476 8.808 34.56 ;
    END
  END s_qpop
  PIN svc_h[0]
    DIRECTION INPUT ;
    USE SIGNAL ;
    PORT
      LAYER M5 ;
        RECT  12.96 0 12.984 0.084 ;
    END
  END svc_h[0]
  PIN svc_h[10]
    DIRECTION INPUT ;
    USE SIGNAL ;
    PORT
      LAYER M5 ;
        RECT  14.4 0 14.424 0.084 ;
    END
  END svc_h[10]
  PIN svc_h[11]
    DIRECTION INPUT ;
    USE SIGNAL ;
    PORT
      LAYER M5 ;
        RECT  29.52 0 29.544 0.084 ;
    END
  END svc_h[11]
  PIN svc_h[12]
    DIRECTION INPUT ;
    USE SIGNAL ;
    PORT
      LAYER M5 ;
        RECT  29.664 0 29.688 0.084 ;
    END
  END svc_h[12]
  PIN svc_h[13]
    DIRECTION INPUT ;
    USE SIGNAL ;
    PORT
      LAYER M5 ;
        RECT  29.808 0 29.832 0.084 ;
    END
  END svc_h[13]
  PIN svc_h[14]
    DIRECTION INPUT ;
    USE SIGNAL ;
    PORT
      LAYER M5 ;
        RECT  29.952 0 29.976 0.084 ;
    END
  END svc_h[14]
  PIN svc_h[15]
    DIRECTION INPUT ;
    USE SIGNAL ;
    PORT
      LAYER M5 ;
        RECT  30.096 0 30.12 0.084 ;
    END
  END svc_h[15]
  PIN svc_h[16]
    DIRECTION INPUT ;
    USE SIGNAL ;
    PORT
      LAYER M5 ;
        RECT  30.24 0 30.264 0.084 ;
    END
  END svc_h[16]
  PIN svc_h[17]
    DIRECTION INPUT ;
    USE SIGNAL ;
    PORT
      LAYER M5 ;
        RECT  30.384 0 30.408 0.084 ;
    END
  END svc_h[17]
  PIN svc_h[18]
    DIRECTION INPUT ;
    USE SIGNAL ;
    PORT
      LAYER M5 ;
        RECT  30.528 0 30.552 0.084 ;
    END
  END svc_h[18]
  PIN svc_h[19]
    DIRECTION INPUT ;
    USE SIGNAL ;
    PORT
      LAYER M5 ;
        RECT  30.672 0 30.696 0.084 ;
    END
  END svc_h[19]
  PIN svc_h[1]
    DIRECTION INPUT ;
    USE SIGNAL ;
    PORT
      LAYER M5 ;
        RECT  13.104 0 13.128 0.084 ;
    END
  END svc_h[1]
  PIN svc_h[20]
    DIRECTION INPUT ;
    USE SIGNAL ;
    PORT
      LAYER M5 ;
        RECT  30.816 0 30.84 0.084 ;
    END
  END svc_h[20]
  PIN svc_h[21]
    DIRECTION INPUT ;
    USE SIGNAL ;
    PORT
      LAYER M5 ;
        RECT  30.96 0 30.984 0.084 ;
    END
  END svc_h[21]
  PIN svc_h[22]
    DIRECTION INPUT ;
    USE SIGNAL ;
    PORT
      LAYER M5 ;
        RECT  31.104 0 31.128 0.084 ;
    END
  END svc_h[22]
  PIN svc_h[23]
    DIRECTION INPUT ;
    USE SIGNAL ;
    PORT
      LAYER M5 ;
        RECT  31.248 0 31.272 0.084 ;
    END
  END svc_h[23]
  PIN svc_h[24]
    DIRECTION INPUT ;
    USE SIGNAL ;
    PORT
      LAYER M5 ;
        RECT  31.392 0 31.416 0.084 ;
    END
  END svc_h[24]
  PIN svc_h[25]
    DIRECTION INPUT ;
    USE SIGNAL ;
    PORT
      LAYER M5 ;
        RECT  31.536 0 31.56 0.084 ;
    END
  END svc_h[25]
  PIN svc_h[26]
    DIRECTION INPUT ;
    USE SIGNAL ;
    PORT
      LAYER M5 ;
        RECT  31.68 0 31.704 0.084 ;
    END
  END svc_h[26]
  PIN svc_h[27]
    DIRECTION INPUT ;
    USE SIGNAL ;
    PORT
      LAYER M5 ;
        RECT  31.824 0 31.848 0.084 ;
    END
  END svc_h[27]
  PIN svc_h[28]
    DIRECTION INPUT ;
    USE SIGNAL ;
    PORT
      LAYER M5 ;
        RECT  31.968 0 31.992 0.084 ;
    END
  END svc_h[28]
  PIN svc_h[29]
    DIRECTION INPUT ;
    USE SIGNAL ;
    PORT
      LAYER M5 ;
        RECT  32.112 0 32.136 0.084 ;
    END
  END svc_h[29]
  PIN svc_h[2]
    DIRECTION INPUT ;
    USE SIGNAL ;
    PORT
      LAYER M5 ;
        RECT  13.248 0 13.272 0.084 ;
    END
  END svc_h[2]
  PIN svc_h[30]
    DIRECTION INPUT ;
    USE SIGNAL ;
    PORT
      LAYER M5 ;
        RECT  32.256 0 32.28 0.084 ;
    END
  END svc_h[30]
  PIN svc_h[31]
    DIRECTION INPUT ;
    USE SIGNAL ;
    PORT
      LAYER M5 ;
        RECT  32.4 0 32.424 0.084 ;
    END
  END svc_h[31]
  PIN svc_h[32]
    DIRECTION INPUT ;
    USE SIGNAL ;
    PORT
      LAYER M5 ;
        RECT  32.544 0 32.568 0.084 ;
    END
  END svc_h[32]
  PIN svc_h[33]
    DIRECTION INPUT ;
    USE SIGNAL ;
    PORT
      LAYER M5 ;
        RECT  32.688 0 32.712 0.084 ;
    END
  END svc_h[33]
  PIN svc_h[34]
    DIRECTION INPUT ;
    USE SIGNAL ;
    PORT
      LAYER M5 ;
        RECT  32.832 0 32.856 0.084 ;
    END
  END svc_h[34]
  PIN svc_h[35]
    DIRECTION INPUT ;
    USE SIGNAL ;
    PORT
      LAYER M5 ;
        RECT  32.976 0 33 0.084 ;
    END
  END svc_h[35]
  PIN svc_h[36]
    DIRECTION INPUT ;
    USE SIGNAL ;
    PORT
      LAYER M5 ;
        RECT  33.12 0 33.144 0.084 ;
    END
  END svc_h[36]
  PIN svc_h[37]
    DIRECTION INPUT ;
    USE SIGNAL ;
    PORT
      LAYER M5 ;
        RECT  33.264 0 33.288 0.084 ;
    END
  END svc_h[37]
  PIN svc_h[38]
    DIRECTION INPUT ;
    USE SIGNAL ;
    PORT
      LAYER M5 ;
        RECT  33.408 0 33.432 0.084 ;
    END
  END svc_h[38]
  PIN svc_h[39]
    DIRECTION INPUT ;
    USE SIGNAL ;
    PORT
      LAYER M5 ;
        RECT  33.552 0 33.576 0.084 ;
    END
  END svc_h[39]
  PIN svc_h[3]
    DIRECTION INPUT ;
    USE SIGNAL ;
    PORT
      LAYER M5 ;
        RECT  13.392 0 13.416 0.084 ;
    END
  END svc_h[3]
  PIN svc_h[40]
    DIRECTION INPUT ;
    USE SIGNAL ;
    PORT
      LAYER M5 ;
        RECT  33.696 0 33.72 0.084 ;
    END
  END svc_h[40]
  PIN svc_h[41]
    DIRECTION INPUT ;
    USE SIGNAL ;
    PORT
      LAYER M5 ;
        RECT  33.84 0 33.864 0.084 ;
    END
  END svc_h[41]
  PIN svc_h[42]
    DIRECTION INPUT ;
    USE SIGNAL ;
    PORT
      LAYER M5 ;
        RECT  33.984 0 34.008 0.084 ;
    END
  END svc_h[42]
  PIN svc_h[43]
    DIRECTION INPUT ;
    USE SIGNAL ;
    PORT
      LAYER M5 ;
        RECT  34.128 0 34.152 0.084 ;
    END
  END svc_h[43]
  PIN svc_h[44]
    DIRECTION INPUT ;
    USE SIGNAL ;
    PORT
      LAYER M5 ;
        RECT  34.272 0 34.296 0.084 ;
    END
  END svc_h[44]
  PIN svc_h[45]
    DIRECTION INPUT ;
    USE SIGNAL ;
    PORT
      LAYER M5 ;
        RECT  34.416 0 34.44 0.084 ;
    END
  END svc_h[45]
  PIN svc_h[46]
    DIRECTION INPUT ;
    USE SIGNAL ;
    PORT
      LAYER M5 ;
        RECT  34.56 0 34.584 0.084 ;
    END
  END svc_h[46]
  PIN svc_h[47]
    DIRECTION INPUT ;
    USE SIGNAL ;
    PORT
      LAYER M5 ;
        RECT  34.704 0 34.728 0.084 ;
    END
  END svc_h[47]
  PIN svc_h[48]
    DIRECTION INPUT ;
    USE SIGNAL ;
    PORT
      LAYER M5 ;
        RECT  34.848 0 34.872 0.084 ;
    END
  END svc_h[48]
  PIN svc_h[49]
    DIRECTION INPUT ;
    USE SIGNAL ;
    PORT
      LAYER M5 ;
        RECT  34.992 0 35.016 0.084 ;
    END
  END svc_h[49]
  PIN svc_h[4]
    DIRECTION INPUT ;
    USE SIGNAL ;
    PORT
      LAYER M5 ;
        RECT  13.536 0 13.56 0.084 ;
    END
  END svc_h[4]
  PIN svc_h[50]
    DIRECTION INPUT ;
    USE SIGNAL ;
    PORT
      LAYER M5 ;
        RECT  35.136 0 35.16 0.084 ;
    END
  END svc_h[50]
  PIN svc_h[51]
    DIRECTION INPUT ;
    USE SIGNAL ;
    PORT
      LAYER M5 ;
        RECT  35.28 0 35.304 0.084 ;
    END
  END svc_h[51]
  PIN svc_h[52]
    DIRECTION INPUT ;
    USE SIGNAL ;
    PORT
      LAYER M5 ;
        RECT  35.424 0 35.448 0.084 ;
    END
  END svc_h[52]
  PIN svc_h[53]
    DIRECTION INPUT ;
    USE SIGNAL ;
    PORT
      LAYER M5 ;
        RECT  35.568 0 35.592 0.084 ;
    END
  END svc_h[53]
  PIN svc_h[54]
    DIRECTION INPUT ;
    USE SIGNAL ;
    PORT
      LAYER M5 ;
        RECT  35.712 0 35.736 0.084 ;
    END
  END svc_h[54]
  PIN svc_h[55]
    DIRECTION INPUT ;
    USE SIGNAL ;
    PORT
      LAYER M5 ;
        RECT  35.856 0 35.88 0.084 ;
    END
  END svc_h[55]
  PIN svc_h[56]
    DIRECTION INPUT ;
    USE SIGNAL ;
    PORT
      LAYER M5 ;
        RECT  36 0 36.024 0.084 ;
    END
  END svc_h[56]
  PIN svc_h[57]
    DIRECTION INPUT ;
    USE SIGNAL ;
    PORT
      LAYER M5 ;
        RECT  36.144 0 36.168 0.084 ;
    END
  END svc_h[57]
  PIN svc_h[58]
    DIRECTION INPUT ;
    USE SIGNAL ;
    PORT
      LAYER M5 ;
        RECT  36.288 0 36.312 0.084 ;
    END
  END svc_h[58]
  PIN svc_h[59]
    DIRECTION INPUT ;
    USE SIGNAL ;
    PORT
      LAYER M5 ;
        RECT  36.432 0 36.456 0.084 ;
    END
  END svc_h[59]
  PIN svc_h[5]
    DIRECTION INPUT ;
    USE SIGNAL ;
    PORT
      LAYER M5 ;
        RECT  13.68 0 13.704 0.084 ;
    END
  END svc_h[5]
  PIN svc_h[60]
    DIRECTION INPUT ;
    USE SIGNAL ;
    PORT
      LAYER M5 ;
        RECT  36.576 0 36.6 0.084 ;
    END
  END svc_h[60]
  PIN svc_h[61]
    DIRECTION INPUT ;
    USE SIGNAL ;
    PORT
      LAYER M5 ;
        RECT  36.72 0 36.744 0.084 ;
    END
  END svc_h[61]
  PIN svc_h[62]
    DIRECTION INPUT ;
    USE SIGNAL ;
    PORT
      LAYER M5 ;
        RECT  36.864 0 36.888 0.084 ;
    END
  END svc_h[62]
  PIN svc_h[63]
    DIRECTION INPUT ;
    USE SIGNAL ;
    PORT
      LAYER M5 ;
        RECT  37.008 0 37.032 0.084 ;
    END
  END svc_h[63]
  PIN svc_h[64]
    DIRECTION INPUT ;
    USE SIGNAL ;
    PORT
      LAYER M5 ;
        RECT  37.152 0 37.176 0.084 ;
    END
  END svc_h[64]
  PIN svc_h[65]
    DIRECTION INPUT ;
    USE SIGNAL ;
    PORT
      LAYER M5 ;
        RECT  37.296 0 37.32 0.084 ;
    END
  END svc_h[65]
  PIN svc_h[66]
    DIRECTION INPUT ;
    USE SIGNAL ;
    PORT
      LAYER M5 ;
        RECT  37.44 0 37.464 0.084 ;
    END
  END svc_h[66]
  PIN svc_h[67]
    DIRECTION INPUT ;
    USE SIGNAL ;
    PORT
      LAYER M5 ;
        RECT  37.584 0 37.608 0.084 ;
    END
  END svc_h[67]
  PIN svc_h[68]
    DIRECTION INPUT ;
    USE SIGNAL ;
    PORT
      LAYER M5 ;
        RECT  37.728 0 37.752 0.084 ;
    END
  END svc_h[68]
  PIN svc_h[69]
    DIRECTION INPUT ;
    USE SIGNAL ;
    PORT
      LAYER M5 ;
        RECT  37.872 0 37.896 0.084 ;
    END
  END svc_h[69]
  PIN svc_h[6]
    DIRECTION INPUT ;
    USE SIGNAL ;
    PORT
      LAYER M5 ;
        RECT  13.824 0 13.848 0.084 ;
    END
  END svc_h[6]
  PIN svc_h[70]
    DIRECTION INPUT ;
    USE SIGNAL ;
    PORT
      LAYER M5 ;
        RECT  38.016 0 38.04 0.084 ;
    END
  END svc_h[70]
  PIN svc_h[71]
    DIRECTION INPUT ;
    USE SIGNAL ;
    PORT
      LAYER M5 ;
        RECT  38.16 0 38.184 0.084 ;
    END
  END svc_h[71]
  PIN svc_h[72]
    DIRECTION INPUT ;
    USE SIGNAL ;
    PORT
      LAYER M5 ;
        RECT  38.304 0 38.328 0.084 ;
    END
  END svc_h[72]
  PIN svc_h[73]
    DIRECTION INPUT ;
    USE SIGNAL ;
    PORT
      LAYER M5 ;
        RECT  38.448 0 38.472 0.084 ;
    END
  END svc_h[73]
  PIN svc_h[74]
    DIRECTION INPUT ;
    USE SIGNAL ;
    PORT
      LAYER M5 ;
        RECT  38.592 0 38.616 0.084 ;
    END
  END svc_h[74]
  PIN svc_h[75]
    DIRECTION INPUT ;
    USE SIGNAL ;
    PORT
      LAYER M5 ;
        RECT  19.152 0 19.176 0.084 ;
    END
  END svc_h[75]
  PIN svc_h[76]
    DIRECTION INPUT ;
    USE SIGNAL ;
    PORT
      LAYER M5 ;
        RECT  19.296 0 19.32 0.084 ;
    END
  END svc_h[76]
  PIN svc_h[77]
    DIRECTION INPUT ;
    USE SIGNAL ;
    PORT
      LAYER M5 ;
        RECT  19.44 0 19.464 0.084 ;
    END
  END svc_h[77]
  PIN svc_h[78]
    DIRECTION INPUT ;
    USE SIGNAL ;
    PORT
      LAYER M5 ;
        RECT  19.584 0 19.608 0.084 ;
    END
  END svc_h[78]
  PIN svc_h[79]
    DIRECTION INPUT ;
    USE SIGNAL ;
    PORT
      LAYER M5 ;
        RECT  19.728 0 19.752 0.084 ;
    END
  END svc_h[79]
  PIN svc_h[7]
    DIRECTION INPUT ;
    USE SIGNAL ;
    PORT
      LAYER M5 ;
        RECT  13.968 0 13.992 0.084 ;
    END
  END svc_h[7]
  PIN svc_h[80]
    DIRECTION INPUT ;
    USE SIGNAL ;
    PORT
      LAYER M5 ;
        RECT  19.872 0 19.896 0.084 ;
    END
  END svc_h[80]
  PIN svc_h[81]
    DIRECTION INPUT ;
    USE SIGNAL ;
    PORT
      LAYER M5 ;
        RECT  20.016 0 20.04 0.084 ;
    END
  END svc_h[81]
  PIN svc_h[82]
    DIRECTION INPUT ;
    USE SIGNAL ;
    PORT
      LAYER M5 ;
        RECT  20.16 0 20.184 0.084 ;
    END
  END svc_h[82]
  PIN svc_h[83]
    DIRECTION INPUT ;
    USE SIGNAL ;
    PORT
      LAYER M5 ;
        RECT  20.304 0 20.328 0.084 ;
    END
  END svc_h[83]
  PIN svc_h[84]
    DIRECTION INPUT ;
    USE SIGNAL ;
    PORT
      LAYER M5 ;
        RECT  20.448 0 20.472 0.084 ;
    END
  END svc_h[84]
  PIN svc_h[85]
    DIRECTION INPUT ;
    USE SIGNAL ;
    PORT
      LAYER M5 ;
        RECT  20.592 0 20.616 0.084 ;
    END
  END svc_h[85]
  PIN svc_h[86]
    DIRECTION INPUT ;
    USE SIGNAL ;
    PORT
      LAYER M5 ;
        RECT  20.736 0 20.76 0.084 ;
    END
  END svc_h[86]
  PIN svc_h[87]
    DIRECTION INPUT ;
    USE SIGNAL ;
    PORT
      LAYER M5 ;
        RECT  20.88 0 20.904 0.084 ;
    END
  END svc_h[87]
  PIN svc_h[8]
    DIRECTION INPUT ;
    USE SIGNAL ;
    PORT
      LAYER M5 ;
        RECT  14.112 0 14.136 0.084 ;
    END
  END svc_h[8]
  PIN svc_h[9]
    DIRECTION INPUT ;
    USE SIGNAL ;
    PORT
      LAYER M5 ;
        RECT  14.256 0 14.28 0.084 ;
    END
  END svc_h[9]
  PIN tk[0]
    DIRECTION OUTPUT ;
    USE SIGNAL ;
    PORT
      LAYER M5 ;
        RECT  21.024 0 21.048 0.084 ;
    END
  END tk[0]
  PIN tk[10]
    DIRECTION OUTPUT ;
    USE SIGNAL ;
    PORT
      LAYER M5 ;
        RECT  22.464 0 22.488 0.084 ;
    END
  END tk[10]
  PIN tk[11]
    DIRECTION OUTPUT ;
    USE SIGNAL ;
    PORT
      LAYER M5 ;
        RECT  22.608 0 22.632 0.084 ;
    END
  END tk[11]
  PIN tk[12]
    DIRECTION OUTPUT ;
    USE SIGNAL ;
    PORT
      LAYER M5 ;
        RECT  22.752 0 22.776 0.084 ;
    END
  END tk[12]
  PIN tk[13]
    DIRECTION OUTPUT ;
    USE SIGNAL ;
    PORT
      LAYER M5 ;
        RECT  22.896 0 22.92 0.084 ;
    END
  END tk[13]
  PIN tk[14]
    DIRECTION OUTPUT ;
    USE SIGNAL ;
    PORT
      LAYER M5 ;
        RECT  23.04 0 23.064 0.084 ;
    END
  END tk[14]
  PIN tk[15]
    DIRECTION OUTPUT ;
    USE SIGNAL ;
    PORT
      LAYER M5 ;
        RECT  23.184 0 23.208 0.084 ;
    END
  END tk[15]
  PIN tk[16]
    DIRECTION OUTPUT ;
    USE SIGNAL ;
    PORT
      LAYER M5 ;
        RECT  23.328 0 23.352 0.084 ;
    END
  END tk[16]
  PIN tk[17]
    DIRECTION OUTPUT ;
    USE SIGNAL ;
    PORT
      LAYER M5 ;
        RECT  23.472 0 23.496 0.084 ;
    END
  END tk[17]
  PIN tk[18]
    DIRECTION OUTPUT ;
    USE SIGNAL ;
    PORT
      LAYER M5 ;
        RECT  23.616 0 23.64 0.084 ;
    END
  END tk[18]
  PIN tk[19]
    DIRECTION OUTPUT ;
    USE SIGNAL ;
    PORT
      LAYER M5 ;
        RECT  23.76 0 23.784 0.084 ;
    END
  END tk[19]
  PIN tk[1]
    DIRECTION OUTPUT ;
    USE SIGNAL ;
    PORT
      LAYER M5 ;
        RECT  21.168 0 21.192 0.084 ;
    END
  END tk[1]
  PIN tk[20]
    DIRECTION OUTPUT ;
    USE SIGNAL ;
    PORT
      LAYER M5 ;
        RECT  23.904 0 23.928 0.084 ;
    END
  END tk[20]
  PIN tk[21]
    DIRECTION OUTPUT ;
    USE SIGNAL ;
    PORT
      LAYER M5 ;
        RECT  24.048 0 24.072 0.084 ;
    END
  END tk[21]
  PIN tk[22]
    DIRECTION OUTPUT ;
    USE SIGNAL ;
    PORT
      LAYER M5 ;
        RECT  24.192 0 24.216 0.084 ;
    END
  END tk[22]
  PIN tk[23]
    DIRECTION OUTPUT ;
    USE SIGNAL ;
    PORT
      LAYER M5 ;
        RECT  24.336 0 24.36 0.084 ;
    END
  END tk[23]
  PIN tk[24]
    DIRECTION OUTPUT ;
    USE SIGNAL ;
    PORT
      LAYER M5 ;
        RECT  24.48 0 24.504 0.084 ;
    END
  END tk[24]
  PIN tk[25]
    DIRECTION OUTPUT ;
    USE SIGNAL ;
    PORT
      LAYER M5 ;
        RECT  24.624 0 24.648 0.084 ;
    END
  END tk[25]
  PIN tk[26]
    DIRECTION OUTPUT ;
    USE SIGNAL ;
    PORT
      LAYER M5 ;
        RECT  24.768 0 24.792 0.084 ;
    END
  END tk[26]
  PIN tk[27]
    DIRECTION OUTPUT ;
    USE SIGNAL ;
    PORT
      LAYER M5 ;
        RECT  24.912 0 24.936 0.084 ;
    END
  END tk[27]
  PIN tk[28]
    DIRECTION OUTPUT ;
    USE SIGNAL ;
    PORT
      LAYER M5 ;
        RECT  25.056 0 25.08 0.084 ;
    END
  END tk[28]
  PIN tk[29]
    DIRECTION OUTPUT ;
    USE SIGNAL ;
    PORT
      LAYER M5 ;
        RECT  25.2 0 25.224 0.084 ;
    END
  END tk[29]
  PIN tk[2]
    DIRECTION OUTPUT ;
    USE SIGNAL ;
    PORT
      LAYER M5 ;
        RECT  21.312 0 21.336 0.084 ;
    END
  END tk[2]
  PIN tk[30]
    DIRECTION OUTPUT ;
    USE SIGNAL ;
    PORT
      LAYER M5 ;
        RECT  25.344 0 25.368 0.084 ;
    END
  END tk[30]
  PIN tk[31]
    DIRECTION OUTPUT ;
    USE SIGNAL ;
    PORT
      LAYER M5 ;
        RECT  25.488 0 25.512 0.084 ;
    END
  END tk[31]
  PIN tk[32]
    DIRECTION OUTPUT ;
    USE SIGNAL ;
    PORT
      LAYER M5 ;
        RECT  25.632 0 25.656 0.084 ;
    END
  END tk[32]
  PIN tk[33]
    DIRECTION OUTPUT ;
    USE SIGNAL ;
    PORT
      LAYER M5 ;
        RECT  25.776 0 25.8 0.084 ;
    END
  END tk[33]
  PIN tk[34]
    DIRECTION OUTPUT ;
    USE SIGNAL ;
    PORT
      LAYER M5 ;
        RECT  25.92 0 25.944 0.084 ;
    END
  END tk[34]
  PIN tk[35]
    DIRECTION OUTPUT ;
    USE SIGNAL ;
    PORT
      LAYER M5 ;
        RECT  26.064 0 26.088 0.084 ;
    END
  END tk[35]
  PIN tk[36]
    DIRECTION OUTPUT ;
    USE SIGNAL ;
    PORT
      LAYER M5 ;
        RECT  26.208 0 26.232 0.084 ;
    END
  END tk[36]
  PIN tk[37]
    DIRECTION OUTPUT ;
    USE SIGNAL ;
    PORT
      LAYER M5 ;
        RECT  26.352 0 26.376 0.084 ;
    END
  END tk[37]
  PIN tk[38]
    DIRECTION OUTPUT ;
    USE SIGNAL ;
    PORT
      LAYER M5 ;
        RECT  26.496 0 26.52 0.084 ;
    END
  END tk[38]
  PIN tk[39]
    DIRECTION OUTPUT ;
    USE SIGNAL ;
    PORT
      LAYER M5 ;
        RECT  26.64 0 26.664 0.084 ;
    END
  END tk[39]
  PIN tk[3]
    DIRECTION OUTPUT ;
    USE SIGNAL ;
    PORT
      LAYER M5 ;
        RECT  21.456 0 21.48 0.084 ;
    END
  END tk[3]
  PIN tk[40]
    DIRECTION OUTPUT ;
    USE SIGNAL ;
    PORT
      LAYER M5 ;
        RECT  26.784 0 26.808 0.084 ;
    END
  END tk[40]
  PIN tk[41]
    DIRECTION OUTPUT ;
    USE SIGNAL ;
    PORT
      LAYER M5 ;
        RECT  26.928 0 26.952 0.084 ;
    END
  END tk[41]
  PIN tk[42]
    DIRECTION OUTPUT ;
    USE SIGNAL ;
    PORT
      LAYER M5 ;
        RECT  27.072 0 27.096 0.084 ;
    END
  END tk[42]
  PIN tk[43]
    DIRECTION OUTPUT ;
    USE SIGNAL ;
    PORT
      LAYER M5 ;
        RECT  27.216 0 27.24 0.084 ;
    END
  END tk[43]
  PIN tk[44]
    DIRECTION OUTPUT ;
    USE SIGNAL ;
    PORT
      LAYER M5 ;
        RECT  27.36 0 27.384 0.084 ;
    END
  END tk[44]
  PIN tk[45]
    DIRECTION OUTPUT ;
    USE SIGNAL ;
    PORT
      LAYER M5 ;
        RECT  27.504 0 27.528 0.084 ;
    END
  END tk[45]
  PIN tk[46]
    DIRECTION OUTPUT ;
    USE SIGNAL ;
    PORT
      LAYER M5 ;
        RECT  27.648 0 27.672 0.084 ;
    END
  END tk[46]
  PIN tk[47]
    DIRECTION OUTPUT ;
    USE SIGNAL ;
    PORT
      LAYER M5 ;
        RECT  27.792 0 27.816 0.084 ;
    END
  END tk[47]
  PIN tk[48]
    DIRECTION OUTPUT ;
    USE SIGNAL ;
    PORT
      LAYER M5 ;
        RECT  27.936 0 27.96 0.084 ;
    END
  END tk[48]
  PIN tk[49]
    DIRECTION OUTPUT ;
    USE SIGNAL ;
    PORT
      LAYER M5 ;
        RECT  28.08 0 28.104 0.084 ;
    END
  END tk[49]
  PIN tk[4]
    DIRECTION OUTPUT ;
    USE SIGNAL ;
    PORT
      LAYER M5 ;
        RECT  21.6 0 21.624 0.084 ;
    END
  END tk[4]
  PIN tk[50]
    DIRECTION OUTPUT ;
    USE SIGNAL ;
    PORT
      LAYER M5 ;
        RECT  28.224 0 28.248 0.084 ;
    END
  END tk[50]
  PIN tk[51]
    DIRECTION OUTPUT ;
    USE SIGNAL ;
    PORT
      LAYER M5 ;
        RECT  14.544 0 14.568 0.084 ;
    END
  END tk[51]
  PIN tk[52]
    DIRECTION OUTPUT ;
    USE SIGNAL ;
    PORT
      LAYER M5 ;
        RECT  14.688 0 14.712 0.084 ;
    END
  END tk[52]
  PIN tk[53]
    DIRECTION OUTPUT ;
    USE SIGNAL ;
    PORT
      LAYER M5 ;
        RECT  14.832 0 14.856 0.084 ;
    END
  END tk[53]
  PIN tk[54]
    DIRECTION OUTPUT ;
    USE SIGNAL ;
    PORT
      LAYER M5 ;
        RECT  14.976 0 15 0.084 ;
    END
  END tk[54]
  PIN tk[55]
    DIRECTION OUTPUT ;
    USE SIGNAL ;
    PORT
      LAYER M5 ;
        RECT  15.12 0 15.144 0.084 ;
    END
  END tk[55]
  PIN tk[56]
    DIRECTION OUTPUT ;
    USE SIGNAL ;
    PORT
      LAYER M5 ;
        RECT  15.264 0 15.288 0.084 ;
    END
  END tk[56]
  PIN tk[57]
    DIRECTION OUTPUT ;
    USE SIGNAL ;
    PORT
      LAYER M5 ;
        RECT  15.408 0 15.432 0.084 ;
    END
  END tk[57]
  PIN tk[58]
    DIRECTION OUTPUT ;
    USE SIGNAL ;
    PORT
      LAYER M5 ;
        RECT  15.552 0 15.576 0.084 ;
    END
  END tk[58]
  PIN tk[59]
    DIRECTION OUTPUT ;
    USE SIGNAL ;
    PORT
      LAYER M5 ;
        RECT  15.696 0 15.72 0.084 ;
    END
  END tk[59]
  PIN tk[5]
    DIRECTION OUTPUT ;
    USE SIGNAL ;
    PORT
      LAYER M5 ;
        RECT  21.744 0 21.768 0.084 ;
    END
  END tk[5]
  PIN tk[60]
    DIRECTION OUTPUT ;
    USE SIGNAL ;
    PORT
      LAYER M5 ;
        RECT  15.84 0 15.864 0.084 ;
    END
  END tk[60]
  PIN tk[61]
    DIRECTION OUTPUT ;
    USE SIGNAL ;
    PORT
      LAYER M5 ;
        RECT  15.984 0 16.008 0.084 ;
    END
  END tk[61]
  PIN tk[62]
    DIRECTION OUTPUT ;
    USE SIGNAL ;
    PORT
      LAYER M5 ;
        RECT  16.128 0 16.152 0.084 ;
    END
  END tk[62]
  PIN tk[63]
    DIRECTION OUTPUT ;
    USE SIGNAL ;
    PORT
      LAYER M5 ;
        RECT  16.272 0 16.296 0.084 ;
    END
  END tk[63]
  PIN tk[64]
    DIRECTION OUTPUT ;
    USE SIGNAL ;
    PORT
      LAYER M5 ;
        RECT  16.416 0 16.44 0.084 ;
    END
  END tk[64]
  PIN tk[65]
    DIRECTION OUTPUT ;
    USE SIGNAL ;
    PORT
      LAYER M5 ;
        RECT  16.56 0 16.584 0.084 ;
    END
  END tk[65]
  PIN tk[66]
    DIRECTION OUTPUT ;
    USE SIGNAL ;
    PORT
      LAYER M5 ;
        RECT  16.704 0 16.728 0.084 ;
    END
  END tk[66]
  PIN tk[67]
    DIRECTION OUTPUT ;
    USE SIGNAL ;
    PORT
      LAYER M5 ;
        RECT  16.848 0 16.872 0.084 ;
    END
  END tk[67]
  PIN tk[68]
    DIRECTION OUTPUT ;
    USE SIGNAL ;
    PORT
      LAYER M5 ;
        RECT  16.992 0 17.016 0.084 ;
    END
  END tk[68]
  PIN tk[69]
    DIRECTION OUTPUT ;
    USE SIGNAL ;
    PORT
      LAYER M5 ;
        RECT  17.136 0 17.16 0.084 ;
    END
  END tk[69]
  PIN tk[6]
    DIRECTION OUTPUT ;
    USE SIGNAL ;
    PORT
      LAYER M5 ;
        RECT  21.888 0 21.912 0.084 ;
    END
  END tk[6]
  PIN tk[70]
    DIRECTION OUTPUT ;
    USE SIGNAL ;
    PORT
      LAYER M5 ;
        RECT  17.28 0 17.304 0.084 ;
    END
  END tk[70]
  PIN tk[71]
    DIRECTION OUTPUT ;
    USE SIGNAL ;
    PORT
      LAYER M5 ;
        RECT  17.424 0 17.448 0.084 ;
    END
  END tk[71]
  PIN tk[72]
    DIRECTION OUTPUT ;
    USE SIGNAL ;
    PORT
      LAYER M5 ;
        RECT  17.568 0 17.592 0.084 ;
    END
  END tk[72]
  PIN tk[73]
    DIRECTION OUTPUT ;
    USE SIGNAL ;
    PORT
      LAYER M5 ;
        RECT  17.712 0 17.736 0.084 ;
    END
  END tk[73]
  PIN tk[74]
    DIRECTION OUTPUT ;
    USE SIGNAL ;
    PORT
      LAYER M5 ;
        RECT  17.856 0 17.88 0.084 ;
    END
  END tk[74]
  PIN tk[75]
    DIRECTION OUTPUT ;
    USE SIGNAL ;
    PORT
      LAYER M5 ;
        RECT  18 0 18.024 0.084 ;
    END
  END tk[75]
  PIN tk[76]
    DIRECTION OUTPUT ;
    USE SIGNAL ;
    PORT
      LAYER M5 ;
        RECT  18.144 0 18.168 0.084 ;
    END
  END tk[76]
  PIN tk[77]
    DIRECTION OUTPUT ;
    USE SIGNAL ;
    PORT
      LAYER M5 ;
        RECT  18.288 0 18.312 0.084 ;
    END
  END tk[77]
  PIN tk[78]
    DIRECTION OUTPUT ;
    USE SIGNAL ;
    PORT
      LAYER M5 ;
        RECT  18.432 0 18.456 0.084 ;
    END
  END tk[78]
  PIN tk[79]
    DIRECTION OUTPUT ;
    USE SIGNAL ;
    PORT
      LAYER M5 ;
        RECT  18.576 0 18.6 0.084 ;
    END
  END tk[79]
  PIN tk[7]
    DIRECTION OUTPUT ;
    USE SIGNAL ;
    PORT
      LAYER M5 ;
        RECT  22.032 0 22.056 0.084 ;
    END
  END tk[7]
  PIN tk[80]
    DIRECTION OUTPUT ;
    USE SIGNAL ;
    PORT
      LAYER M5 ;
        RECT  18.72 0 18.744 0.084 ;
    END
  END tk[80]
  PIN tk[81]
    DIRECTION OUTPUT ;
    USE SIGNAL ;
    PORT
      LAYER M5 ;
        RECT  18.864 0 18.888 0.084 ;
    END
  END tk[81]
  PIN tk[82]
    DIRECTION OUTPUT ;
    USE SIGNAL ;
    PORT
      LAYER M5 ;
        RECT  19.008 0 19.032 0.084 ;
    END
  END tk[82]
  PIN tk[83]
    DIRECTION OUTPUT ;
    USE SIGNAL ;
    PORT
      LAYER M5 ;
        RECT  5.328 0 5.352 0.084 ;
    END
  END tk[83]
  PIN tk[84]
    DIRECTION OUTPUT ;
    USE SIGNAL ;
    PORT
      LAYER M5 ;
        RECT  5.472 0 5.496 0.084 ;
    END
  END tk[84]
  PIN tk[85]
    DIRECTION OUTPUT ;
    USE SIGNAL ;
    PORT
      LAYER M5 ;
        RECT  5.616 0 5.64 0.084 ;
    END
  END tk[85]
  PIN tk[86]
    DIRECTION OUTPUT ;
    USE SIGNAL ;
    PORT
      LAYER M5 ;
        RECT  5.76 0 5.784 0.084 ;
    END
  END tk[86]
  PIN tk[87]
    DIRECTION OUTPUT ;
    USE SIGNAL ;
    PORT
      LAYER M5 ;
        RECT  5.904 0 5.928 0.084 ;
    END
  END tk[87]
  PIN tk[88]
    DIRECTION OUTPUT ;
    USE SIGNAL ;
    PORT
      LAYER M5 ;
        RECT  6.048 0 6.072 0.084 ;
    END
  END tk[88]
  PIN tk[89]
    DIRECTION OUTPUT ;
    USE SIGNAL ;
    PORT
      LAYER M5 ;
        RECT  6.192 0 6.216 0.084 ;
    END
  END tk[89]
  PIN tk[8]
    DIRECTION OUTPUT ;
    USE SIGNAL ;
    PORT
      LAYER M5 ;
        RECT  22.176 0 22.2 0.084 ;
    END
  END tk[8]
  PIN tk[90]
    DIRECTION OUTPUT ;
    USE SIGNAL ;
    PORT
      LAYER M5 ;
        RECT  6.336 0 6.36 0.084 ;
    END
  END tk[90]
  PIN tk[91]
    DIRECTION OUTPUT ;
    USE SIGNAL ;
    PORT
      LAYER M5 ;
        RECT  6.48 0 6.504 0.084 ;
    END
  END tk[91]
  PIN tk[92]
    DIRECTION OUTPUT ;
    USE SIGNAL ;
    PORT
      LAYER M5 ;
        RECT  6.624 0 6.648 0.084 ;
    END
  END tk[92]
  PIN tk[9]
    DIRECTION OUTPUT ;
    USE SIGNAL ;
    PORT
      LAYER M5 ;
        RECT  22.32 0 22.344 0.084 ;
    END
  END tk[9]
  PIN x_v
    DIRECTION OUTPUT ;
    USE SIGNAL ;
    PORT
      LAYER M5 ;
        RECT  8.928 34.476 8.952 34.56 ;
    END
  END x_v
  PIN VDD
    DIRECTION INOUT ;
    USE POWER ;
    PORT
      LAYER M5 ;
        RECT  40.392 2.151 40.512 32.409 ;
        RECT  37.692 2.151 37.812 32.409 ;
        RECT  34.992 2.151 35.112 32.409 ;
        RECT  32.292 2.151 32.412 32.409 ;
        RECT  29.592 2.151 29.712 32.409 ;
        RECT  26.892 2.151 27.012 32.409 ;
        RECT  24.192 2.151 24.312 32.409 ;
        RECT  21.492 2.151 21.612 32.409 ;
        RECT  18.792 2.151 18.912 32.409 ;
        RECT  16.092 2.151 16.212 32.409 ;
        RECT  13.392 2.151 13.512 32.409 ;
        RECT  10.692 2.151 10.812 32.409 ;
        RECT  7.992 2.151 8.112 32.409 ;
        RECT  5.292 2.151 5.412 32.409 ;
        RECT  2.592 2.151 2.712 32.409 ;
    END
  END VDD
  PIN VSS
    DIRECTION INOUT ;
    USE GROUND ;
    PORT
      LAYER M5 ;
        RECT  40.2 2.137 40.32 32.423 ;
        RECT  37.5 2.137 37.62 32.423 ;
        RECT  34.8 2.137 34.92 32.423 ;
        RECT  32.1 2.137 32.22 32.423 ;
        RECT  29.4 2.137 29.52 32.423 ;
        RECT  26.7 2.137 26.82 32.423 ;
        RECT  24 2.137 24.12 32.423 ;
        RECT  21.3 2.137 21.42 32.423 ;
        RECT  18.6 2.137 18.72 32.423 ;
        RECT  15.9 2.137 16.02 32.423 ;
        RECT  13.2 2.137 13.32 32.423 ;
        RECT  10.5 2.137 10.62 32.423 ;
        RECT  7.8 2.137 7.92 32.423 ;
        RECT  5.1 2.137 5.22 32.423 ;
        RECT  2.4 2.137 2.52 32.423 ;
    END
  END VSS
  OBS
    LAYER RVTN ;
     RECT  2.16 2.16 41.04 2.295 ;
     RECT  2.16 2.565 41.04 2.835 ;
     RECT  2.16 3.105 41.04 3.375 ;
     RECT  2.16 3.645 41.04 3.915 ;
     RECT  2.16 4.185 41.04 4.455 ;
     RECT  2.16 4.725 41.04 4.995 ;
     RECT  2.16 5.265 41.04 5.535 ;
     RECT  2.16 5.805 41.04 6.075 ;
     RECT  2.16 6.345 41.04 6.615 ;
     RECT  2.16 6.885 41.04 7.155 ;
     RECT  2.16 7.425 41.04 7.695 ;
     RECT  2.16 7.965 41.04 8.235 ;
     RECT  2.16 8.505 41.04 8.775 ;
     RECT  2.16 9.045 41.04 9.315 ;
     RECT  2.16 9.585 41.04 9.855 ;
     RECT  2.16 10.125 41.04 10.395 ;
     RECT  2.16 10.665 41.04 10.935 ;
     RECT  2.16 11.205 41.04 11.475 ;
     RECT  2.16 11.745 41.04 12.015 ;
     RECT  2.16 12.285 41.04 12.555 ;
     RECT  2.16 12.825 41.04 13.095 ;
     RECT  2.16 13.365 41.04 13.635 ;
     RECT  2.16 13.905 41.04 14.175 ;
     RECT  2.16 14.445 41.04 14.715 ;
     RECT  2.16 14.985 41.04 15.255 ;
     RECT  2.16 15.525 41.04 15.795 ;
     RECT  2.16 16.065 41.04 16.335 ;
     RECT  2.16 16.605 41.04 16.875 ;
     RECT  2.16 17.145 41.04 17.415 ;
     RECT  2.16 17.685 41.04 17.955 ;
     RECT  2.16 18.225 41.04 18.495 ;
     RECT  2.16 18.765 41.04 19.035 ;
     RECT  2.16 19.305 41.04 19.575 ;
     RECT  2.16 19.845 41.04 20.115 ;
     RECT  2.16 20.385 41.04 20.655 ;
     RECT  2.16 20.925 41.04 21.195 ;
     RECT  2.16 21.465 41.04 21.735 ;
     RECT  2.16 22.005 41.04 22.275 ;
     RECT  2.16 22.545 41.04 22.815 ;
     RECT  2.16 23.085 41.04 23.355 ;
     RECT  2.16 23.625 41.04 23.895 ;
     RECT  2.16 24.165 41.04 24.435 ;
     RECT  2.16 24.705 41.04 24.975 ;
     RECT  2.16 25.245 41.04 25.515 ;
     RECT  2.16 25.785 41.04 26.055 ;
     RECT  2.16 26.325 41.04 26.595 ;
     RECT  2.16 26.865 41.04 27.135 ;
     RECT  2.16 27.405 41.04 27.675 ;
     RECT  2.16 27.945 41.04 28.215 ;
     RECT  2.16 28.485 41.04 28.755 ;
     RECT  2.16 29.025 41.04 29.295 ;
     RECT  2.16 29.565 41.04 29.835 ;
     RECT  2.16 30.105 41.04 30.375 ;
     RECT  2.16 30.645 41.04 30.915 ;
     RECT  2.16 31.185 41.04 31.455 ;
     RECT  2.16 31.725 41.04 31.995 ;
     RECT  2.16 32.265 41.04 32.4 ;
    LAYER RVTP ;
     RECT  2.16 2.295 41.04 2.565 ;
     RECT  2.16 2.835 41.04 3.105 ;
     RECT  2.16 3.375 41.04 3.645 ;
     RECT  2.16 3.915 41.04 4.185 ;
     RECT  2.16 4.455 41.04 4.725 ;
     RECT  2.16 4.995 41.04 5.265 ;
     RECT  2.16 5.535 41.04 5.805 ;
     RECT  2.16 6.075 41.04 6.345 ;
     RECT  2.16 6.615 41.04 6.885 ;
     RECT  2.16 7.155 41.04 7.425 ;
     RECT  2.16 7.695 41.04 7.965 ;
     RECT  2.16 8.235 41.04 8.505 ;
     RECT  2.16 8.775 41.04 9.045 ;
     RECT  2.16 9.315 41.04 9.585 ;
     RECT  2.16 9.855 41.04 10.125 ;
     RECT  2.16 10.395 41.04 10.665 ;
     RECT  2.16 10.935 41.04 11.205 ;
     RECT  2.16 11.475 41.04 11.745 ;
     RECT  2.16 12.015 41.04 12.285 ;
     RECT  2.16 12.555 41.04 12.825 ;
     RECT  2.16 13.095 41.04 13.365 ;
     RECT  2.16 13.635 41.04 13.905 ;
     RECT  2.16 14.175 41.04 14.445 ;
     RECT  2.16 14.715 41.04 14.985 ;
     RECT  2.16 15.255 41.04 15.525 ;
     RECT  2.16 15.795 41.04 16.065 ;
     RECT  2.16 16.335 41.04 16.605 ;
     RECT  2.16 16.875 41.04 17.145 ;
     RECT  2.16 17.415 41.04 17.685 ;
     RECT  2.16 17.955 41.04 18.225 ;
     RECT  2.16 18.495 41.04 18.765 ;
     RECT  2.16 19.035 41.04 19.305 ;
     RECT  2.16 19.575 41.04 19.845 ;
     RECT  2.16 20.115 41.04 20.385 ;
     RECT  2.16 20.655 41.04 20.925 ;
     RECT  2.16 21.195 41.04 21.465 ;
     RECT  2.16 21.735 41.04 22.005 ;
     RECT  2.16 22.275 41.04 22.545 ;
     RECT  2.16 22.815 41.04 23.085 ;
     RECT  2.16 23.355 41.04 23.625 ;
     RECT  2.16 23.895 41.04 24.165 ;
     RECT  2.16 24.435 41.04 24.705 ;
     RECT  2.16 24.975 41.04 25.245 ;
     RECT  2.16 25.515 41.04 25.785 ;
     RECT  2.16 26.055 41.04 26.325 ;
     RECT  2.16 26.595 41.04 26.865 ;
     RECT  2.16 27.135 41.04 27.405 ;
     RECT  2.16 27.675 41.04 27.945 ;
     RECT  2.16 28.215 41.04 28.485 ;
     RECT  2.16 28.755 41.04 29.025 ;
     RECT  2.16 29.295 41.04 29.565 ;
     RECT  2.16 29.835 41.04 30.105 ;
     RECT  2.16 30.375 41.04 30.645 ;
     RECT  2.16 30.915 41.04 31.185 ;
     RECT  2.16 31.455 41.04 31.725 ;
     RECT  2.16 31.995 41.04 32.265 ;
    LAYER M1 ;
     RECT  2.16 2.151 41.04 32.409 ;
    LAYER M2 ;
     RECT  0.103 10.746 0.139 11.394 ;
     RECT  0.139 10.674 0.175 11.394 ;
     RECT  0.103 19.926 0.499 19.944 ;
     RECT  0.499 19.656 0.535 19.944 ;
     RECT  0.499 21.006 0.535 21.024 ;
     RECT  0.535 25.326 0.571 25.344 ;
     RECT  0.103 15.381 0.599 15.399 ;
     RECT  0.103 24.516 0.599 24.534 ;
     RECT  0.175 10.404 2.16 11.394 ;
     RECT  0.139 12.366 2.16 12.384 ;
     RECT  0.571 16.506 2.16 16.524 ;
     RECT  0.535 19.656 2.16 20.142 ;
     RECT  0.535 21.006 2.16 21.294 ;
     RECT  0.571 25.326 2.16 25.812 ;
     RECT  2.16 2.151 8.275 32.409 ;
     RECT  8.275 1.962 10.111 32.409 ;
     RECT  10.111 1.881 10.291 32.409 ;
     RECT  10.291 1.836 14.711 32.409 ;
     RECT  14.711 1.962 16.367 32.409 ;
     RECT  16.367 2.151 17.383 32.409 ;
     RECT  17.383 2.106 18.275 32.409 ;
     RECT  21.919 1.152 22.091 1.17 ;
     RECT  22.819 1.224 22.927 1.242 ;
     RECT  22.927 1.152 22.991 1.242 ;
     RECT  22.991 1.152 23.027 1.17 ;
     RECT  18.275 2.151 23.179 32.409 ;
     RECT  23.179 2.106 24.539 32.409 ;
     RECT  24.539 2.151 27.247 32.409 ;
     RECT  27.355 1.152 27.491 1.17 ;
     RECT  28.327 1.152 28.499 1.17 ;
     RECT  27.247 2.034 28.715 32.409 ;
     RECT  30.235 1.152 30.335 1.17 ;
     RECT  28.715 2.106 30.839 32.409 ;
     RECT  33.835 1.152 33.935 1.17 ;
     RECT  30.839 2.151 41.04 32.409 ;
     RECT  41.04 19.008 41.531 20.484 ;
     RECT  41.04 16.344 41.567 18.054 ;
     RECT  41.531 19.206 41.603 20.484 ;
     RECT  41.04 13.986 41.639 14.544 ;
     RECT  41.04 23.166 41.711 24.228 ;
     RECT  41.04 27.846 42.143 29.934 ;
     RECT  41.603 19.746 42.179 20.484 ;
     RECT  42.143 27.846 42.179 28.314 ;
     RECT  41.04 15.336 42.215 15.552 ;
     RECT  41.567 16.344 42.215 17.982 ;
     RECT  42.179 28.296 42.215 28.314 ;
     RECT  42.215 15.534 42.251 15.552 ;
     RECT  42.143 29.574 42.251 29.934 ;
     RECT  42.215 16.92 42.287 17.982 ;
     RECT  41.711 23.166 42.287 23.922 ;
     RECT  41.04 25.056 42.287 26.388 ;
     RECT  42.251 29.916 42.287 29.934 ;
     RECT  42.179 20.016 43.007 20.484 ;
     RECT  41.639 13.986 43.079 14.472 ;
     RECT  42.287 23.328 43.079 23.922 ;
     RECT  42.287 25.056 43.079 25.074 ;
     RECT  43.079 13.986 43.115 14.004 ;
     RECT  42.287 17.424 43.115 17.982 ;
     RECT  43.007 20.016 43.115 20.142 ;
     RECT  43.079 23.904 43.115 23.922 ;
     RECT  42.287 26.37 43.115 26.388 ;
     RECT  43.115 17.892 43.187 17.91 ;
     RECT  43.115 20.016 43.187 20.034 ;
    LAYER M3 ;
     RECT  15.552 0.043 15.57 0.091 ;
     RECT  17.496 0.091 17.514 0.139 ;
     RECT  18.36 0.091 18.846 0.139 ;
     RECT  22.644 0.091 23.238 0.139 ;
     RECT  28.332 0.091 28.35 0.139 ;
     RECT  15.552 0.091 15.714 0.173 ;
     RECT  28.332 0.139 28.782 0.187 ;
     RECT  27.36 0.091 27.378 0.235 ;
     RECT  28.26 0.187 28.782 0.235 ;
     RECT  11.124 0.187 11.142 0.331 ;
     RECT  9.864 0.283 9.882 0.379 ;
     RECT  10.98 0.331 11.142 0.379 ;
     RECT  12.096 0.091 12.114 0.427 ;
     RECT  13.104 0.091 13.122 0.427 ;
     RECT  9.864 0.379 11.142 0.523 ;
     RECT  12.096 0.427 13.122 0.523 ;
     RECT  14.688 0.091 14.706 0.523 ;
     RECT  15.696 0.173 15.714 0.523 ;
     RECT  31.932 0.043 31.95 0.523 ;
     RECT  5.832 0.091 5.85 0.571 ;
     RECT  18.36 0.139 19.206 0.571 ;
     RECT  8.748 0.043 8.766 0.619 ;
     RECT  9.864 0.523 14.706 0.619 ;
     RECT  5.832 0.571 5.958 1.099 ;
     RECT  6.732 0.091 6.75 1.099 ;
     RECT  27.36 0.235 28.782 1.099 ;
     RECT  15.696 0.523 16.11 1.147 ;
     RECT  30.24 0.523 30.258 1.147 ;
     RECT  33.696 0.091 34.218 1.147 ;
     RECT  21.924 0.139 23.238 1.175 ;
     RECT  5.076 0.091 5.094 1.723 ;
     RECT  5.832 1.099 6.75 1.723 ;
     RECT  15.696 1.147 16.398 1.723 ;
     RECT  17.316 0.139 17.514 1.723 ;
     RECT  18.36 0.571 19.458 1.723 ;
     RECT  27.18 1.099 28.782 1.723 ;
     RECT  30.24 1.147 30.33 1.723 ;
     RECT  31.248 0.523 31.95 1.723 ;
     RECT  33.696 1.147 34.29 1.723 ;
     RECT  35.244 0.091 35.262 1.723 ;
     RECT  27.18 1.723 36.918 1.771 ;
     RECT  37.98 1.723 38.502 1.771 ;
     RECT  37.98 1.771 38.574 1.819 ;
     RECT  8.748 0.619 14.706 1.957 ;
     RECT  27.18 1.771 36.99 1.963 ;
     RECT  37.872 1.819 38.574 1.963 ;
     RECT  8.28 1.957 14.706 2.065 ;
     RECT  15.696 1.723 16.47 2.065 ;
     RECT  24.624 1.195 24.642 2.101 ;
     RECT  8.28 2.065 16.47 2.143 ;
     RECT  17.316 1.723 21.042 2.143 ;
     RECT  22.068 1.175 23.238 2.143 ;
     RECT  24.516 2.101 24.642 2.143 ;
     RECT  27.18 1.963 38.574 2.143 ;
     RECT  39.6 1.723 39.618 2.143 ;
     RECT  5.076 1.723 6.75 2.191 ;
     RECT  7.815 2.143 16.47 2.191 ;
     RECT  17.316 2.143 23.238 2.191 ;
     RECT  24.015 2.143 24.642 2.191 ;
     RECT  25.92 1.147 25.938 2.191 ;
     RECT  26.715 2.143 38.574 2.191 ;
     RECT  5.076 2.191 38.574 2.335 ;
     RECT  39.6 2.143 40.305 2.335 ;
     RECT  2.415 2.143 2.505 2.413 ;
     RECT  5.076 2.335 40.305 2.413 ;
     RECT  5.076 2.413 40.497 2.641 ;
     RECT  5.076 2.641 40.698 2.911 ;
     RECT  5.076 2.911 40.77 3.451 ;
     RECT  4.608 3.451 40.77 3.577 ;
     RECT  4.464 3.577 40.77 3.629 ;
     RECT  5.076 3.629 40.77 4.507 ;
     RECT  4.752 4.507 40.77 5.071 ;
     RECT  4.572 5.071 40.77 5.999 ;
     RECT  7.2 5.999 40.77 6.007 ;
     RECT  2.415 2.413 2.697 6.151 ;
     RECT  3.672 6.115 3.69 6.151 ;
     RECT  2.415 6.151 3.834 6.277 ;
     RECT  7.2 6.007 40.806 6.305 ;
     RECT  2.412 6.277 3.834 6.385 ;
     RECT  4.572 5.999 6.462 6.385 ;
     RECT  2.412 6.385 6.462 6.413 ;
     RECT  7.2 6.305 40.734 6.539 ;
     RECT  2.415 6.413 6.462 6.647 ;
     RECT  3.42 6.647 6.462 6.961 ;
     RECT  7.2 6.539 40.662 6.961 ;
     RECT  3.42 6.961 40.662 7.861 ;
     RECT  2.415 6.647 2.697 7.963 ;
     RECT  3.42 7.861 40.842 7.963 ;
     RECT  2.415 7.963 40.842 8.195 ;
     RECT  37.26 8.195 40.842 8.231 ;
     RECT  2.415 8.195 36.486 8.339 ;
     RECT  37.476 8.231 40.842 8.339 ;
     RECT  2.415 8.339 36.306 8.429 ;
     RECT  18.18 8.429 36.306 8.465 ;
     RECT  37.515 8.339 40.842 8.879 ;
     RECT  38.88 8.879 40.626 8.969 ;
     RECT  37.515 8.879 38.106 9.005 ;
     RECT  40.215 8.969 40.626 9.005 ;
     RECT  37.515 9.005 37.797 9.085 ;
     RECT  34.38 8.465 36.306 9.115 ;
     RECT  2.415 8.429 17.37 9.211 ;
     RECT  18.18 8.465 33.642 9.211 ;
     RECT  2.415 9.211 33.642 9.239 ;
     RECT  40.215 9.005 40.554 9.239 ;
     RECT  38.88 8.969 39.15 9.383 ;
     RECT  20.376 9.239 33.642 9.391 ;
     RECT  34.38 9.115 36.414 9.391 ;
     RECT  20.376 9.391 36.414 9.509 ;
     RECT  38.88 9.383 39.042 9.509 ;
     RECT  2.415 9.239 19.602 9.545 ;
     RECT  34.38 9.509 36.414 9.545 ;
     RECT  38.88 9.509 38.898 9.545 ;
     RECT  22.536 9.509 33.534 9.581 ;
     RECT  30.708 9.581 33.534 9.617 ;
     RECT  30.708 9.617 30.87 9.653 ;
     RECT  31.86 9.617 32.397 9.689 ;
     RECT  33.516 9.617 33.534 9.689 ;
     RECT  30.708 9.653 30.834 9.779 ;
     RECT  30.78 9.779 30.834 9.851 ;
     RECT  30.78 9.851 30.798 10.049 ;
     RECT  3.996 9.545 19.602 10.057 ;
     RECT  20.376 9.509 21.798 10.057 ;
     RECT  34.452 9.545 36.414 10.057 ;
     RECT  37.404 9.085 37.797 10.057 ;
     RECT  34.452 10.057 37.854 10.171 ;
     RECT  34.452 10.171 37.998 10.201 ;
     RECT  3.996 10.057 21.798 10.291 ;
     RECT  22.536 9.581 29.862 10.291 ;
     RECT  34.452 10.201 38.25 10.291 ;
     RECT  2.415 9.545 2.697 10.399 ;
     RECT  33.732 10.291 38.25 10.399 ;
     RECT  2.415 10.399 2.754 10.435 ;
     RECT  33.732 10.399 38.61 10.435 ;
     RECT  3.996 10.291 29.862 10.471 ;
     RECT  33.336 10.435 38.97 10.471 ;
     RECT  3.744 10.471 30.042 10.597 ;
     RECT  32.115 9.689 32.397 10.597 ;
     RECT  33.336 10.471 39.294 10.597 ;
     RECT  0.18 10.399 0.198 10.669 ;
     RECT  2.304 10.435 2.754 10.705 ;
     RECT  3.708 10.597 30.042 10.705 ;
     RECT  32.115 10.597 39.294 10.733 ;
     RECT  0.144 10.669 0.198 10.741 ;
     RECT  2.304 10.705 30.042 10.741 ;
     RECT  32.115 10.733 39.078 10.975 ;
     RECT  2.304 10.741 30.186 11.003 ;
     RECT  32.04 10.975 39.078 11.003 ;
     RECT  0.108 10.741 0.198 11.011 ;
     RECT  32.04 11.003 35.658 11.011 ;
     RECT  31.464 11.011 35.658 11.551 ;
     RECT  36.432 11.003 39.078 11.551 ;
     RECT  36.432 11.551 39.366 11.677 ;
     RECT  40.215 9.239 40.497 11.677 ;
     RECT  2.304 11.003 30.15 11.749 ;
     RECT  2.304 11.749 30.186 11.785 ;
     RECT  31.068 11.551 35.658 11.785 ;
     RECT  2.304 11.785 35.658 11.821 ;
     RECT  36.432 11.677 40.497 11.821 ;
     RECT  2.304 11.821 40.497 11.849 ;
     RECT  2.34 11.849 40.497 11.939 ;
     RECT  31.068 11.939 40.497 11.975 ;
     RECT  31.068 11.975 39.078 12.047 ;
     RECT  0.108 11.011 0.558 12.269 ;
     RECT  0.108 12.269 0.162 12.413 ;
     RECT  2.34 11.939 30.186 12.631 ;
     RECT  2.304 12.631 30.186 12.721 ;
     RECT  31.068 12.047 39.042 12.721 ;
     RECT  39.924 11.975 40.497 12.865 ;
     RECT  2.304 12.721 39.042 12.901 ;
     RECT  39.888 12.865 40.497 12.901 ;
     RECT  2.304 12.901 40.497 13.135 ;
     RECT  2.304 13.135 40.626 13.531 ;
     RECT  2.304 13.531 40.77 13.981 ;
     RECT  0.144 12.413 0.162 14.107 ;
     RECT  2.304 13.981 40.806 14.215 ;
     RECT  0.108 14.107 0.162 14.251 ;
     RECT  0.108 14.251 0.342 14.429 ;
     RECT  43.092 13.981 43.11 14.449 ;
     RECT  2.304 14.215 40.914 14.521 ;
     RECT  41.652 14.071 41.67 14.521 ;
     RECT  43.056 14.449 43.11 14.573 ;
     RECT  2.304 14.521 41.67 15.017 ;
     RECT  43.056 14.573 43.074 15.149 ;
     RECT  2.34 15.017 41.67 15.293 ;
     RECT  0.108 14.429 0.162 15.376 ;
     RECT  42.192 15.331 42.21 15.403 ;
     RECT  0.108 15.376 0.594 15.404 ;
     RECT  42.192 15.403 42.246 15.557 ;
     RECT  2.34 15.293 41.022 15.725 ;
     RECT  2.34 15.725 40.806 16.231 ;
     RECT  2.304 16.231 40.806 16.301 ;
     RECT  42.192 15.557 42.21 16.411 ;
     RECT  0.576 15.404 0.594 16.529 ;
     RECT  2.304 16.301 40.698 16.601 ;
     RECT  2.304 16.601 25.758 16.835 ;
     RECT  42.156 16.411 42.21 16.843 ;
     RECT  41.832 16.843 42.21 16.915 ;
     RECT  2.415 16.835 25.758 17.069 ;
     RECT  15.336 17.069 25.758 17.105 ;
     RECT  41.832 16.915 42.282 17.165 ;
     RECT  41.832 17.165 42.21 17.275 ;
     RECT  15.408 17.105 25.758 17.375 ;
     RECT  41.58 17.275 42.21 17.419 ;
     RECT  15.444 17.375 25.758 17.491 ;
     RECT  26.532 16.601 40.698 17.491 ;
     RECT  3.42 17.069 14.454 17.519 ;
     RECT  43.092 16.987 43.11 17.707 ;
     RECT  42.984 17.707 43.11 17.887 ;
     RECT  41.544 17.419 42.21 18.029 ;
     RECT  2.415 17.069 2.697 18.121 ;
     RECT  3.42 17.519 14.418 18.121 ;
     RECT  2.415 18.121 14.418 18.265 ;
     RECT  15.444 17.491 40.734 18.265 ;
     RECT  2.415 18.265 40.734 18.283 ;
     RECT  41.544 18.029 42.174 18.283 ;
     RECT  2.415 18.283 42.174 18.769 ;
     RECT  2.376 18.769 42.174 19.471 ;
     RECT  2.304 19.471 42.174 19.499 ;
     RECT  28.008 19.499 42.174 19.535 ;
     RECT  28.152 19.535 42.174 19.769 ;
     RECT  0.504 19.651 0.522 19.885 ;
     RECT  0.504 19.885 0.558 19.921 ;
     RECT  28.152 19.769 41.85 19.949 ;
     RECT  42.984 17.887 43.182 20.039 ;
     RECT  28.152 19.949 41.346 20.111 ;
     RECT  42.984 20.039 43.11 20.147 ;
     RECT  2.304 19.499 27.054 20.299 ;
     RECT  41.328 20.111 41.346 20.309 ;
     RECT  28.152 20.111 40.554 20.317 ;
     RECT  2.304 20.299 27.27 20.353 ;
     RECT  28.008 20.317 40.554 20.353 ;
     RECT  42.984 20.147 43.002 20.489 ;
     RECT  2.304 20.353 40.554 21.119 ;
     RECT  0.108 19.921 0.558 21.917 ;
     RECT  0.54 21.917 0.558 22.061 ;
     RECT  2.304 21.119 40.497 22.081 ;
     RECT  2.304 22.081 40.914 22.199 ;
     RECT  0.18 22.891 0.198 23.179 ;
     RECT  42.264 23.161 42.282 23.251 ;
     RECT  0.18 23.179 0.558 23.611 ;
     RECT  2.304 22.199 40.842 23.665 ;
     RECT  2.304 23.665 41.022 23.789 ;
     RECT  42.228 23.251 42.282 23.791 ;
     RECT  42.192 23.791 42.282 23.899 ;
     RECT  43.056 23.323 43.074 23.899 ;
     RECT  43.056 23.899 43.11 24.221 ;
     RECT  41.688 23.899 42.282 24.233 ;
     RECT  2.304 23.789 40.914 24.241 ;
     RECT  2.268 24.241 40.914 24.395 ;
     RECT  0.108 23.611 0.558 24.511 ;
     RECT  0.108 24.511 0.594 24.539 ;
     RECT  2.304 24.395 40.914 24.653 ;
     RECT  2.304 24.653 40.734 24.935 ;
     RECT  43.092 24.221 43.11 25.051 ;
     RECT  0.54 24.539 0.594 25.349 ;
     RECT  20.448 24.935 40.734 25.447 ;
     RECT  2.304 24.935 19.674 25.709 ;
     RECT  2.304 25.709 19.566 25.745 ;
     RECT  43.056 25.051 43.11 25.805 ;
     RECT  0.576 25.349 0.594 25.817 ;
     RECT  3.564 25.745 19.566 25.817 ;
     RECT  42.192 24.233 42.282 25.817 ;
     RECT  42.192 25.817 42.246 25.915 ;
     RECT  2.34 25.745 2.754 26.015 ;
     RECT  2.34 26.015 2.697 26.087 ;
     RECT  41.58 25.915 42.246 26.093 ;
     RECT  20.448 25.447 40.77 26.347 ;
     RECT  41.58 26.093 42.174 26.347 ;
     RECT  43.092 25.805 43.11 26.393 ;
     RECT  3.852 25.817 19.566 26.663 ;
     RECT  3.852 26.663 17.082 26.671 ;
     RECT  17.856 26.663 19.566 26.671 ;
     RECT  20.448 26.347 42.174 26.671 ;
     RECT  17.856 26.671 42.174 26.933 ;
     RECT  17.928 26.933 42.174 27.067 ;
     RECT  2.415 26.087 2.697 27.103 ;
     RECT  3.708 26.671 17.082 27.103 ;
     RECT  17.928 27.067 42.21 27.211 ;
     RECT  17.928 27.211 42.246 27.643 ;
     RECT  2.415 27.103 17.082 27.751 ;
     RECT  17.928 27.643 42.282 27.751 ;
     RECT  2.415 27.751 42.282 28.247 ;
     RECT  37.296 28.247 42.282 28.409 ;
     RECT  2.415 28.247 36.558 28.493 ;
     RECT  37.332 28.409 40.77 29.255 ;
     RECT  37.332 29.255 40.662 29.489 ;
     RECT  41.508 28.409 42.282 29.489 ;
     RECT  37.332 29.489 38.358 29.525 ;
     RECT  37.332 29.525 37.89 29.597 ;
     RECT  42.228 29.489 42.282 29.597 ;
     RECT  2.415 28.493 36.414 29.759 ;
     RECT  39.996 29.489 40.662 29.759 ;
     RECT  39.996 29.759 40.497 29.795 ;
     RECT  42.264 29.597 42.282 29.939 ;
     RECT  18.216 29.759 36.414 30.001 ;
     RECT  37.332 29.597 37.797 30.001 ;
     RECT  2.415 29.759 17.298 30.101 ;
     RECT  4.572 30.101 17.298 30.173 ;
     RECT  18.216 30.001 37.797 30.335 ;
     RECT  18.216 30.335 36.162 30.479 ;
     RECT  2.415 30.101 3.762 30.569 ;
     RECT  4.968 30.173 17.298 30.613 ;
     RECT  18.216 30.479 35.91 30.613 ;
     RECT  2.415 30.569 3.582 30.641 ;
     RECT  4.968 30.613 35.91 30.641 ;
     RECT  4.968 30.641 35.514 30.839 ;
     RECT  2.415 30.641 3.438 30.875 ;
     RECT  4.968 30.839 35.442 30.911 ;
     RECT  3.42 30.875 3.438 30.947 ;
     RECT  36.936 30.335 37.797 30.947 ;
     RECT  4.968 30.911 35.154 30.955 ;
     RECT  4.788 30.955 35.154 31.109 ;
     RECT  4.788 31.109 22.806 31.145 ;
     RECT  4.968 31.145 22.806 31.289 ;
     RECT  24.012 31.109 30.15 31.289 ;
     RECT  24.012 31.289 30.006 31.379 ;
     RECT  30.96 31.109 35.154 31.379 ;
     RECT  4.968 31.289 22.41 31.415 ;
     RECT  30.96 31.379 33.858 31.451 ;
     RECT  25.56 31.379 30.006 31.523 ;
     RECT  24.012 31.379 24.678 31.649 ;
     RECT  25.668 31.523 30.006 31.649 ;
     RECT  31.032 31.451 33.858 31.649 ;
     RECT  4.968 31.415 22.122 31.721 ;
     RECT  25.776 31.649 30.006 31.721 ;
     RECT  31.104 31.649 33.858 31.721 ;
     RECT  31.104 31.721 32.814 31.757 ;
     RECT  33.768 31.721 33.858 31.793 ;
     RECT  24.015 31.649 24.678 31.829 ;
     RECT  31.104 31.757 32.706 31.829 ;
     RECT  4.968 31.721 21.597 31.919 ;
     RECT  25.776 31.721 27.522 31.919 ;
     RECT  31.392 31.829 32.706 31.919 ;
     RECT  33.768 31.793 33.822 31.919 ;
     RECT  18.252 31.919 21.597 31.955 ;
     RECT  26.568 31.919 27.522 31.991 ;
     RECT  28.548 31.721 30.006 31.991 ;
     RECT  31.392 31.919 32.397 31.991 ;
     RECT  33.768 31.919 33.786 31.991 ;
     RECT  25.776 31.919 25.794 31.997 ;
     RECT  4.968 31.919 16.197 32.071 ;
     RECT  28.548 31.991 29.898 32.099 ;
     RECT  31.932 31.991 32.397 32.099 ;
     RECT  2.415 30.875 2.697 32.147 ;
     RECT  4.86 32.071 16.197 32.147 ;
     RECT  18.615 31.955 18.897 32.147 ;
     RECT  20.16 31.955 21.597 32.147 ;
     RECT  24.015 31.829 24.297 32.147 ;
     RECT  32.115 32.099 32.397 32.147 ;
     RECT  34.632 31.379 35.097 32.147 ;
     RECT  37.515 30.947 37.797 32.147 ;
     RECT  40.215 29.795 40.497 32.147 ;
     RECT  4.86 32.147 16.005 32.189 ;
     RECT  17.208 31.919 17.514 32.189 ;
     RECT  20.16 32.147 21.438 32.189 ;
     RECT  26.568 31.991 27.486 32.189 ;
     RECT  28.548 32.099 29.862 32.189 ;
     RECT  32.115 32.147 32.274 32.189 ;
     RECT  34.632 32.147 34.905 32.189 ;
     RECT  17.352 32.189 17.37 32.225 ;
     RECT  28.548 32.189 29.505 32.225 ;
     RECT  29.088 32.225 29.505 32.261 ;
     RECT  4.86 32.189 14.526 32.305 ;
     RECT  4.68 32.305 14.526 32.333 ;
     RECT  20.16 32.189 20.538 32.333 ;
     RECT  20.16 32.333 20.178 32.369 ;
     RECT  2.415 32.147 2.505 32.417 ;
     RECT  15.915 32.189 16.005 32.417 ;
     RECT  18.615 32.147 18.705 32.417 ;
     RECT  21.315 32.189 21.405 32.417 ;
     RECT  24.015 32.147 24.105 32.417 ;
     RECT  26.715 32.189 26.805 32.417 ;
     RECT  29.415 32.261 29.505 32.417 ;
     RECT  32.115 32.189 32.205 32.417 ;
     RECT  34.815 32.189 34.905 32.417 ;
     RECT  37.515 32.147 37.605 32.417 ;
     RECT  40.215 32.147 40.305 32.417 ;
     RECT  4.68 32.333 13.59 32.477 ;
     RECT  14.508 32.333 14.526 32.477 ;
     RECT  5.04 32.477 5.346 32.525 ;
     RECT  7.236 32.477 8.298 32.525 ;
     RECT  12.492 32.477 12.51 32.525 ;
     RECT  13.356 32.477 13.59 32.525 ;
     RECT  5.04 32.525 5.274 32.573 ;
     RECT  7.776 32.525 8.298 32.573 ;
     RECT  9.504 32.477 10.674 32.573 ;
     RECT  13.572 32.525 13.59 32.573 ;
     RECT  9.504 32.573 10.098 33.677 ;
     RECT  8.28 32.573 8.298 34.445 ;
     RECT  10.08 33.677 10.098 34.445 ;
    LAYER M4 ;
     RECT  0.06 10.944 0.137 15.288 ;
     RECT  0.06 20.016 0.569 24.504 ;
     RECT  0.569 20.16 2.365 24.504 ;
     RECT  2.401 6.384 2.408 6.408 ;
     RECT  0.137 11.088 2.408 15.288 ;
     RECT  2.365 19.344 2.408 24.504 ;
     RECT  2.408 2.148 2.512 32.412 ;
     RECT  2.512 2.418 2.704 32.142 ;
     RECT  2.704 11.808 3.305 15.288 ;
     RECT  2.704 6.384 3.449 6.408 ;
     RECT  3.305 11.808 3.521 14.712 ;
     RECT  2.704 29.328 3.557 30.6 ;
     RECT  2.704 18.768 3.629 24.36 ;
     RECT  2.704 27.312 3.74 27.336 ;
     RECT  3.557 29.328 3.805 29.352 ;
     RECT  3.74 26.784 3.877 27.336 ;
     RECT  3.805 28.56 3.877 29.352 ;
     RECT  2.704 7.968 3.913 7.992 ;
     RECT  3.521 12.864 3.917 14.712 ;
     RECT  3.913 7.728 3.953 7.992 ;
     RECT  3.877 26.784 4.057 29.352 ;
     RECT  3.629 20.688 4.093 24.36 ;
     RECT  3.521 11.808 4.381 11.832 ;
     RECT  4.381 11.424 4.417 11.832 ;
     RECT  2.704 16.56 4.508 16.584 ;
     RECT  3.953 7.728 4.525 7.752 ;
     RECT  4.417 11.232 4.525 11.832 ;
     RECT  3.917 12.864 4.525 14.664 ;
     RECT  4.453 3.6 4.549 3.624 ;
     RECT  3.629 18.768 4.669 19.56 ;
     RECT  4.093 20.688 4.669 24.984 ;
     RECT  3.697 17.616 4.7 17.64 ;
     RECT  4.669 18.768 4.7 24.984 ;
     RECT  4.057 26.64 4.837 29.352 ;
     RECT  4.525 11.232 4.885 14.664 ;
     RECT  4.885 11.184 4.993 14.664 ;
     RECT  4.508 15.888 4.993 16.584 ;
     RECT  4.7 17.616 5.029 24.984 ;
     RECT  4.669 32.448 5.029 32.472 ;
     RECT  4.549 3.6 5.108 4.536 ;
     RECT  4.525 7.68 5.108 7.752 ;
     RECT  4.813 9.888 5.108 9.912 ;
     RECT  4.993 11.184 5.108 16.584 ;
     RECT  5.029 17.616 5.108 25.032 ;
     RECT  4.837 26.64 5.108 29.4 ;
     RECT  3.557 30.576 5.108 30.6 ;
     RECT  5.029 32.448 5.108 32.568 ;
     RECT  5.108 2.148 5.281 32.568 ;
     RECT  5.281 1.728 5.285 32.568 ;
     RECT  5.285 1.728 5.363 32.52 ;
     RECT  5.363 1.728 5.404 32.472 ;
     RECT  5.404 20.16 5.465 26.856 ;
     RECT  5.404 27.888 5.465 30.792 ;
     RECT  5.465 20.16 5.537 26.328 ;
     RECT  5.465 29.232 5.645 30.792 ;
     RECT  5.404 3.744 5.651 5.016 ;
     RECT  5.404 7.68 5.651 8.952 ;
     RECT  5.461 34.368 5.699 34.392 ;
     RECT  5.404 31.968 5.753 32.472 ;
     RECT  5.404 17.616 5.825 17.64 ;
     RECT  5.065 0.096 5.885 0.12 ;
     RECT  5.885 0.096 5.969 0.6 ;
     RECT  5.404 6.24 6.041 6.504 ;
     RECT  5.404 1.728 6.083 2.28 ;
     RECT  6.083 1.728 6.14 1.8 ;
     RECT  6.14 1.104 6.227 1.8 ;
     RECT  6.041 6.24 6.293 6.264 ;
     RECT  5.404 11.232 6.293 12.024 ;
     RECT  5.651 3.744 6.397 4.536 ;
     RECT  5.465 27.888 6.565 27.96 ;
     RECT  5.645 29.232 6.565 30.264 ;
     RECT  6.565 27.888 6.577 30.264 ;
     RECT  6.577 27.456 6.611 30.264 ;
     RECT  6.469 7.392 6.613 7.416 ;
     RECT  5.651 8.448 6.613 8.952 ;
     RECT  5.537 20.16 6.613 23.688 ;
     RECT  5.537 24.672 6.613 26.328 ;
     RECT  6.227 1.728 6.653 1.8 ;
     RECT  6.397 3.408 6.721 4.536 ;
     RECT  6.293 11.952 6.721 12.024 ;
     RECT  5.404 13.056 6.721 16.296 ;
     RECT  6.653 1.776 6.725 1.8 ;
     RECT  5.753 32.304 6.749 32.472 ;
     RECT  6.577 10.032 6.757 10.056 ;
     RECT  5.969 0.096 6.761 0.12 ;
     RECT  6.757 9.936 6.793 10.056 ;
     RECT  5.404 18.816 6.793 18.888 ;
     RECT  6.613 20.016 6.793 26.328 ;
     RECT  6.613 7.392 6.803 8.952 ;
     RECT  6.721 11.952 6.829 16.296 ;
     RECT  6.757 17.712 6.829 17.736 ;
     RECT  6.793 18.816 6.829 26.328 ;
     RECT  6.749 32.016 6.829 32.472 ;
     RECT  6.721 3.408 6.833 5.112 ;
     RECT  6.793 9.936 6.853 10.104 ;
     RECT  6.829 11.952 6.901 16.584 ;
     RECT  6.829 17.712 6.901 26.328 ;
     RECT  6.611 27.456 6.901 29.256 ;
     RECT  6.829 31.92 7.225 32.472 ;
     RECT  6.973 5.28 7.297 5.304 ;
     RECT  6.901 17.712 7.369 29.256 ;
     RECT  6.853 9.072 7.381 10.104 ;
     RECT  7.405 30.576 7.505 30.744 ;
     RECT  7.369 17.664 7.593 29.256 ;
     RECT  7.505 30.576 7.593 30.936 ;
     RECT  7.593 17.664 7.621 30.936 ;
     RECT  7.225 31.92 7.621 32.52 ;
     RECT  7.621 34.416 7.669 34.44 ;
     RECT  7.621 17.664 7.765 32.52 ;
     RECT  6.833 3.408 7.808 4.248 ;
     RECT  7.297 5.28 7.808 6.024 ;
     RECT  6.803 7.392 7.808 8.04 ;
     RECT  7.381 9.072 7.808 10.2 ;
     RECT  6.901 11.952 7.808 16.68 ;
     RECT  7.765 17.664 7.808 32.568 ;
     RECT  7.808 2.148 7.849 32.568 ;
     RECT  7.849 2.148 7.912 32.52 ;
     RECT  7.912 2.418 8.104 32.52 ;
     RECT  8.104 5.472 8.165 6.84 ;
     RECT  8.104 31.2 8.237 32.52 ;
     RECT  7.669 34.32 8.309 34.44 ;
     RECT  8.104 17.376 8.417 17.688 ;
     RECT  8.104 19.584 8.489 29.784 ;
     RECT  8.489 20.112 8.525 29.784 ;
     RECT  8.525 21.168 8.633 29.784 ;
     RECT  8.104 9.6 8.705 16.344 ;
     RECT  8.633 21.168 8.705 29.256 ;
     RECT  8.104 2.544 8.716 4.392 ;
     RECT  8.237 31.2 8.741 32.472 ;
     RECT  8.705 9.6 8.993 15.288 ;
     RECT  8.705 16.32 9.209 16.344 ;
     RECT  8.716 2.544 9.245 4.248 ;
     RECT  8.741 31.92 9.251 32.472 ;
     RECT  8.737 0.048 9.385 0.072 ;
     RECT  9.251 32.016 9.397 32.472 ;
     RECT  8.773 33.648 9.533 33.672 ;
     RECT  8.165 5.76 9.637 6.84 ;
     RECT  9.596 8.256 9.637 8.28 ;
     RECT  8.705 26.784 9.673 29.256 ;
     RECT  9.245 3.84 9.817 4.248 ;
     RECT  8.525 20.112 10.033 20.136 ;
     RECT  8.705 21.168 10.033 25.752 ;
     RECT  9.245 2.544 10.069 2.856 ;
     RECT  9.673 26.784 10.069 29.352 ;
     RECT  9.397 32.016 10.213 32.04 ;
     RECT  10.069 1.728 10.285 2.856 ;
     RECT  9.817 3.84 10.285 4.536 ;
     RECT  10.213 31.92 10.321 32.04 ;
     RECT  9.385 0.048 10.357 0.648 ;
     RECT  10.285 1.728 10.357 4.536 ;
     RECT  9.637 5.76 10.465 8.28 ;
     RECT  10.321 31.776 10.465 32.04 ;
     RECT  10.357 0.048 10.508 4.536 ;
     RECT  10.465 5.568 10.508 8.28 ;
     RECT  8.993 10.176 10.508 15.288 ;
     RECT  8.417 17.376 10.508 17.4 ;
     RECT  10.033 20.064 10.508 25.752 ;
     RECT  10.069 26.784 10.508 29.64 ;
     RECT  10.465 31.776 10.508 32.568 ;
     RECT  10.508 0.048 10.729 32.568 ;
     RECT  10.729 0.048 10.804 32.472 ;
     RECT  10.069 34.416 10.835 34.44 ;
     RECT  10.804 0.048 11.369 8.28 ;
     RECT  10.804 11.664 11.452 16.008 ;
     RECT  10.804 26.784 11.621 30.408 ;
     RECT  11.452 11.664 11.833 15.48 ;
     RECT  11.621 27.216 11.9 30.408 ;
     RECT  11.9 27.216 11.987 30.6 ;
     RECT  10.804 17.376 12.121 17.4 ;
     RECT  12.049 18.528 12.121 18.552 ;
     RECT  11.369 2.544 12.193 8.28 ;
     RECT  12.121 17.376 12.277 18.552 ;
     RECT  12.193 2.544 12.409 8.568 ;
     RECT  10.804 31.92 12.421 32.472 ;
     RECT  12.421 31.344 12.476 32.472 ;
     RECT  11.369 0.048 12.563 1.224 ;
     RECT  10.804 20.016 12.589 25.704 ;
     RECT  11.833 10.848 12.841 15.48 ;
     RECT  12.409 2.496 12.913 8.568 ;
     RECT  12.277 17.136 12.913 18.552 ;
     RECT  11.987 27.216 12.985 30.264 ;
     RECT  12.913 9.6 13.057 9.624 ;
     RECT  12.841 10.848 13.057 15.96 ;
     RECT  12.589 20.016 13.057 26.232 ;
     RECT  12.985 27.216 13.057 30.312 ;
     RECT  12.913 1.728 13.208 8.568 ;
     RECT  13.057 9.6 13.208 15.96 ;
     RECT  12.913 17.136 13.208 18.792 ;
     RECT  13.057 20.016 13.208 30.312 ;
     RECT  12.476 31.344 13.208 32.52 ;
     RECT  13.208 1.728 13.237 32.52 ;
     RECT  13.237 1.728 13.504 32.568 ;
     RECT  13.504 19.824 13.601 29.832 ;
     RECT  13.504 32.304 13.601 32.568 ;
     RECT  13.525 34.416 13.667 34.44 ;
     RECT  13.601 32.304 13.889 32.472 ;
     RECT  13.504 16.656 13.925 18.792 ;
     RECT  13.504 1.728 14.141 7.416 ;
     RECT  13.601 19.824 14.249 25.656 ;
     RECT  13.504 10.368 14.285 15.576 ;
     RECT  13.925 16.656 14.429 17.688 ;
     RECT  14.141 1.776 14.465 7.416 ;
     RECT  13.889 32.448 14.537 32.472 ;
     RECT  12.563 0.048 14.579 0.552 ;
     RECT  14.285 10.368 14.645 12.84 ;
     RECT  14.465 6.528 14.713 7.416 ;
     RECT  13.601 27.312 14.749 29.832 ;
     RECT  14.749 27.072 14.821 29.832 ;
     RECT  13.504 31.104 14.821 31.128 ;
     RECT  14.465 1.776 14.825 5.064 ;
     RECT  14.821 27.072 15.061 31.128 ;
     RECT  14.713 6.528 15.068 7.8 ;
     RECT  13.504 8.88 15.068 9.144 ;
     RECT  15.061 27.072 15.109 31.8 ;
     RECT  14.249 20.064 15.217 25.656 ;
     RECT  14.645 11.184 15.325 12.84 ;
     RECT  14.285 13.872 15.325 15.576 ;
     RECT  15.217 20.064 15.325 25.848 ;
     RECT  13.925 18.768 15.361 18.792 ;
     RECT  15.361 18.768 15.397 18.84 ;
     RECT  15.325 19.872 15.397 25.848 ;
     RECT  15.109 26.88 15.397 31.8 ;
     RECT  15.068 6.528 15.541 9.144 ;
     RECT  15.397 18.48 15.541 18.84 ;
     RECT  14.579 0.048 15.581 0.456 ;
     RECT  15.541 18.432 15.613 18.84 ;
     RECT  15.397 19.872 15.613 31.8 ;
     RECT  15.541 6.24 15.721 9.144 ;
     RECT  15.581 0.096 15.769 0.456 ;
     RECT  15.325 11.184 15.865 15.576 ;
     RECT  15.769 0.192 15.875 0.456 ;
     RECT  14.825 1.776 15.908 4.536 ;
     RECT  15.721 6.096 15.908 9.624 ;
     RECT  15.865 10.704 15.908 15.576 ;
     RECT  14.429 16.656 15.908 17.4 ;
     RECT  15.613 18.432 15.908 31.8 ;
     RECT  15.875 0.432 15.973 0.456 ;
     RECT  15.908 1.776 16.012 32.412 ;
     RECT  15.973 0.432 16.163 0.552 ;
     RECT  16.012 1.776 16.204 32.142 ;
     RECT  16.204 19.872 16.265 29.832 ;
     RECT  16.204 3.408 16.355 7.752 ;
     RECT  16.261 1.152 16.409 1.752 ;
     RECT  16.265 20.064 16.517 29.832 ;
     RECT  16.517 20.064 16.769 29.544 ;
     RECT  16.769 26.256 16.877 29.544 ;
     RECT  16.355 3.648 17.027 7.752 ;
     RECT  16.877 26.304 17.057 29.544 ;
     RECT  16.204 10.704 17.093 15.336 ;
     RECT  16.981 0.096 17.125 0.12 ;
     RECT  16.409 1.728 17.269 1.752 ;
     RECT  16.204 8.928 17.273 9.624 ;
     RECT  17.027 5.568 17.305 7.752 ;
     RECT  17.057 26.352 17.309 29.544 ;
     RECT  17.125 0.096 17.345 0.168 ;
     RECT  17.309 26.352 17.345 29.304 ;
     RECT  16.204 30.816 17.345 31.8 ;
     RECT  17.269 1.728 17.381 2.328 ;
     RECT  16.204 16.416 17.453 18.84 ;
     RECT  17.273 8.976 17.561 9.624 ;
     RECT  17.093 10.896 17.701 15.336 ;
     RECT  17.453 16.416 17.701 17.688 ;
     RECT  17.381 1.728 17.849 1.8 ;
     RECT  17.027 3.648 18.133 4.584 ;
     RECT  17.345 26.352 18.277 29.016 ;
     RECT  17.345 0.096 18.38 0.12 ;
     RECT  18.133 2.928 18.421 4.584 ;
     RECT  17.305 5.568 18.421 7.896 ;
     RECT  17.345 30.816 18.469 31.272 ;
     RECT  16.769 20.064 18.493 25.272 ;
     RECT  18.277 26.256 18.493 29.016 ;
     RECT  18.493 20.064 18.565 29.016 ;
     RECT  18.469 30 18.565 31.272 ;
     RECT  17.849 1.776 18.608 1.8 ;
     RECT  18.421 2.928 18.608 7.896 ;
     RECT  17.561 8.976 18.608 9.576 ;
     RECT  17.701 10.896 18.608 17.688 ;
     RECT  17.453 18.816 18.608 18.84 ;
     RECT  18.565 20.064 18.608 31.272 ;
     RECT  18.608 1.776 18.712 32.412 ;
     RECT  18.38 0.096 18.857 0.552 ;
     RECT  18.712 1.776 18.904 32.142 ;
     RECT  18.857 0.144 18.997 0.552 ;
     RECT  18.997 0.144 19.217 0.648 ;
     RECT  18.904 1.776 19.277 2.328 ;
     RECT  18.904 19.248 19.469 27.912 ;
     RECT  19.469 19.92 19.505 27.912 ;
     RECT  19.217 0.576 19.513 0.648 ;
     RECT  18.904 3.936 19.613 9.576 ;
     RECT  19.613 3.936 19.649 9.096 ;
     RECT  18.904 28.992 19.685 29.64 ;
     RECT  19.277 1.728 19.763 2.328 ;
     RECT  18.904 11.76 19.897 15.576 ;
     RECT  19.763 1.728 19.907 2.28 ;
     RECT  18.904 10.608 19.933 10.632 ;
     RECT  19.897 11.712 19.933 15.576 ;
     RECT  19.513 0.624 19.955 0.648 ;
     RECT  19.933 10.608 19.957 15.576 ;
     RECT  19.685 29.616 20.077 29.64 ;
     RECT  19.505 19.92 20.081 25.272 ;
     RECT  19.505 26.256 20.189 27.912 ;
     RECT  18.904 16.8 20.257 17.496 ;
     RECT  20.077 29.616 20.293 30.504 ;
     RECT  18.904 31.92 20.293 31.944 ;
     RECT  19.957 10.128 20.329 15.576 ;
     RECT  20.257 16.8 20.329 17.976 ;
     RECT  20.293 29.616 20.333 31.944 ;
     RECT  20.333 29.616 20.339 31.368 ;
     RECT  19.907 1.728 20.972 2.232 ;
     RECT  19.649 4.128 20.977 9.096 ;
     RECT  20.972 1.728 21.053 2.28 ;
     RECT  20.977 3.552 21.109 9.096 ;
     RECT  20.081 20.064 21.193 25.272 ;
     RECT  20.189 26.256 21.193 27.192 ;
     RECT  21.053 1.824 21.308 2.28 ;
     RECT  21.109 3.408 21.308 9.096 ;
     RECT  20.329 10.128 21.308 17.976 ;
     RECT  21.193 20.064 21.308 27.192 ;
     RECT  20.339 29.616 21.308 29.64 ;
     RECT  20.339 31.344 21.308 31.368 ;
     RECT  21.308 1.824 21.412 32.412 ;
     RECT  21.412 1.824 21.491 32.142 ;
     RECT  21.491 2.016 21.604 32.142 ;
     RECT  21.604 2.016 21.701 9.096 ;
     RECT  21.109 0.144 21.733 0.168 ;
     RECT  21.733 0.096 22.309 0.168 ;
     RECT  22.309 0.096 22.405 0.216 ;
     RECT  21.701 2.016 22.453 2.856 ;
     RECT  22.405 0.096 22.597 0.264 ;
     RECT  22.453 1.728 22.597 2.856 ;
     RECT  21.604 30.768 22.637 30.84 ;
     RECT  21.701 3.984 22.669 9.096 ;
     RECT  21.604 10.128 22.669 17.4 ;
     RECT  22.669 3.984 22.813 17.4 ;
     RECT  22.597 0.096 22.817 2.856 ;
     RECT  22.817 2.256 23.029 2.856 ;
     RECT  22.813 3.984 23.029 17.64 ;
     RECT  22.817 0.096 23.069 1.176 ;
     RECT  21.604 20.064 23.173 26.808 ;
     RECT  23.173 20.064 23.209 27.144 ;
     RECT  23.069 0.096 23.249 0.12 ;
     RECT  23.029 2.256 23.281 17.64 ;
     RECT  23.069 1.152 23.363 1.176 ;
     RECT  23.209 20.064 23.461 27.384 ;
     RECT  23.461 19.632 23.569 27.384 ;
     RECT  22.637 30.768 24.001 30.792 ;
     RECT  23.281 2.256 24.008 18.168 ;
     RECT  23.569 19.344 24.008 27.384 ;
     RECT  21.604 29.616 24.008 29.64 ;
     RECT  24.001 30.768 24.008 31.416 ;
     RECT  24.008 2.148 24.112 32.412 ;
     RECT  24.112 2.256 24.304 32.142 ;
     RECT  24.037 0.192 24.373 0.408 ;
     RECT  24.373 0.144 24.515 1.176 ;
     RECT  24.304 2.256 24.563 15.384 ;
     RECT  24.515 0.192 24.613 1.176 ;
     RECT  24.613 0.192 24.697 1.224 ;
     RECT  24.304 16.368 24.947 29.064 ;
     RECT  24.304 30.096 25.085 31.416 ;
     RECT  25.085 30.576 25.139 31.416 ;
     RECT  24.947 16.416 25.381 29.064 ;
     RECT  25.381 16.416 25.468 29.4 ;
     RECT  24.697 0.192 25.477 1.176 ;
     RECT  24.563 2.256 25.525 2.28 ;
     RECT  24.563 3.408 25.525 15.384 ;
     RECT  25.468 16.416 25.661 29.256 ;
     RECT  25.525 2.256 25.715 15.384 ;
     RECT  25.477 0.144 26.197 1.176 ;
     RECT  25.661 20.064 26.521 29.256 ;
     RECT  25.139 30.576 26.521 30.6 ;
     RECT  26.197 0.144 26.708 1.752 ;
     RECT  25.715 2.88 26.708 15.384 ;
     RECT  25.661 16.416 26.708 18.552 ;
     RECT  26.521 20.064 26.708 30.6 ;
     RECT  25.765 31.968 26.708 31.992 ;
     RECT  26.708 0.144 26.812 32.412 ;
     RECT  26.812 0.144 26.917 32.142 ;
     RECT  26.917 0.096 27.004 32.142 ;
     RECT  27.004 0.096 27.209 1.752 ;
     RECT  27.004 16.608 27.245 30.936 ;
     RECT  27.245 19.2 27.251 30.936 ;
     RECT  27.004 10.896 27.317 12.84 ;
     RECT  27.245 16.608 27.317 18.216 ;
     RECT  27.317 11.136 27.461 12.84 ;
     RECT  27.004 13.92 27.461 15.288 ;
     RECT  27.004 2.88 27.532 9.912 ;
     RECT  27.209 0.096 27.929 0.504 ;
     RECT  27.532 2.88 28.217 3.096 ;
     RECT  27.209 1.728 28.253 1.752 ;
     RECT  27.929 0.096 28.309 0.264 ;
     RECT  28.309 0.048 28.355 0.264 ;
     RECT  27.251 20.064 28.357 30.936 ;
     RECT  27.004 31.968 28.357 31.992 ;
     RECT  27.461 11.76 28.573 12.84 ;
     RECT  28.217 2.928 28.753 3.096 ;
     RECT  27.532 4.128 28.753 9.912 ;
     RECT  28.573 11.52 28.753 12.84 ;
     RECT  27.461 13.968 28.789 15.288 ;
     RECT  28.355 0.048 28.793 0.168 ;
     RECT  28.753 2.928 28.977 9.912 ;
     RECT  28.753 11.136 28.977 12.84 ;
     RECT  28.789 13.968 29.005 15.624 ;
     RECT  27.317 16.608 29.005 17.64 ;
     RECT  28.429 18.816 29.005 18.84 ;
     RECT  29.293 1.728 29.408 1.752 ;
     RECT  28.977 2.928 29.408 12.84 ;
     RECT  29.005 13.968 29.408 17.64 ;
     RECT  29.005 18.816 29.408 18.888 ;
     RECT  28.357 20.064 29.408 31.992 ;
     RECT  29.408 1.728 29.512 32.412 ;
     RECT  29.512 1.728 29.704 32.142 ;
     RECT  29.704 10.176 29.765 17.064 ;
     RECT  29.704 1.728 29.801 9.144 ;
     RECT  29.801 1.728 29.837 2.904 ;
     RECT  29.765 10.176 29.873 10.2 ;
     RECT  29.765 11.76 29.945 17.064 ;
     RECT  29.704 30.576 30.017 31.176 ;
     RECT  28.793 0.048 30.188 0.072 ;
     RECT  29.945 11.76 30.269 15.576 ;
     RECT  30.188 0.048 30.275 0.552 ;
     RECT  29.945 16.656 30.629 17.064 ;
     RECT  29.704 18.816 30.697 20.424 ;
     RECT  29.704 21.504 30.697 29.496 ;
     RECT  30.697 18.816 30.757 29.496 ;
     RECT  30.017 30.576 30.757 31.08 ;
     RECT  29.801 4.128 30.769 9.144 ;
     RECT  29.837 2.88 30.773 2.904 ;
     RECT  30.757 18.816 30.803 31.08 ;
     RECT  30.803 18.816 30.881 29.64 ;
     RECT  29.837 1.728 30.949 1.752 ;
     RECT  30.269 13.872 30.985 15.576 ;
     RECT  30.629 16.656 30.985 16.68 ;
     RECT  30.881 18.816 31.057 29.304 ;
     RECT  30.275 0.048 31.237 0.072 ;
     RECT  30.803 30.624 31.285 31.08 ;
     RECT  30.269 11.76 31.333 12.84 ;
     RECT  30.985 13.872 31.333 16.68 ;
     RECT  31.237 0.048 31.571 0.552 ;
     RECT  31.333 11.712 31.885 16.68 ;
     RECT  30.949 1.728 31.909 2.232 ;
     RECT  30.769 4.128 31.957 9.288 ;
     RECT  31.571 0.048 31.961 0.168 ;
     RECT  31.909 1.728 32.108 3.048 ;
     RECT  31.957 4.128 32.108 9.624 ;
     RECT  31.885 11.136 32.108 16.68 ;
     RECT  31.057 18.768 32.108 29.304 ;
     RECT  31.285 30.624 32.108 31.944 ;
     RECT  31.961 0.144 32.147 0.168 ;
     RECT  32.108 1.728 32.212 32.412 ;
     RECT  32.212 1.728 32.404 32.142 ;
     RECT  32.404 3.744 32.429 9.288 ;
     RECT  32.404 1.728 32.531 2.04 ;
     RECT  32.404 19.488 32.573 20.664 ;
     RECT  32.404 10.464 32.645 11.784 ;
     RECT  32.404 30.384 32.723 30.984 ;
     RECT  32.531 1.728 32.867 1.848 ;
     RECT  32.404 13.872 33.077 17.64 ;
     RECT  32.573 19.776 33.077 20.664 ;
     RECT  33.109 0.096 33.541 0.12 ;
     RECT  32.867 1.728 33.545 1.8 ;
     RECT  33.077 19.776 33.545 20.568 ;
     RECT  32.723 30.672 33.577 30.984 ;
     RECT  32.429 3.744 33.589 9.048 ;
     RECT  33.589 3.744 33.685 9.384 ;
     RECT  33.577 30.672 33.757 31.272 ;
     RECT  32.404 21.984 34.009 29.304 ;
     RECT  33.757 30.672 34.009 31.368 ;
     RECT  32.404 12.816 34.117 12.84 ;
     RECT  33.077 13.872 34.117 16.824 ;
     RECT  33.541 0.096 34.229 0.168 ;
     RECT  33.545 1.728 34.261 1.752 ;
     RECT  32.645 10.464 34.261 11.592 ;
     RECT  34.261 10.464 34.441 11.736 ;
     RECT  34.117 12.816 34.441 16.824 ;
     RECT  33.545 20.112 34.549 20.568 ;
     RECT  33.685 3.072 34.693 9.384 ;
     RECT  34.261 1.152 34.808 1.752 ;
     RECT  34.693 2.88 34.808 9.384 ;
     RECT  34.441 10.464 34.808 16.824 ;
     RECT  33.721 18.096 34.808 18.552 ;
     RECT  34.549 19.632 34.808 20.568 ;
     RECT  34.009 21.984 34.808 31.368 ;
     RECT  34.808 1.152 34.912 32.412 ;
     RECT  34.229 0.144 34.981 0.168 ;
     RECT  34.912 1.152 34.981 32.142 ;
     RECT  34.981 0.144 35.104 32.142 ;
     RECT  35.104 3.024 35.165 19.032 ;
     RECT  35.104 0.144 35.218 1.848 ;
     RECT  35.165 3.024 35.219 17.64 ;
     RECT  35.219 3.024 35.267 10.824 ;
     RECT  35.218 0.096 35.315 1.848 ;
     RECT  35.315 0.096 35.317 0.12 ;
     RECT  35.104 21.84 35.363 30.072 ;
     RECT  35.267 3.216 35.404 10.824 ;
     RECT  35.219 12.048 35.417 17.64 ;
     RECT  35.363 29.088 35.705 30.072 ;
     RECT  35.404 3.216 35.891 9 ;
     RECT  35.404 10.128 35.939 10.824 ;
     RECT  35.165 18.768 36.085 19.032 ;
     RECT  35.104 20.304 36.085 20.328 ;
     RECT  35.315 1.728 36.097 1.848 ;
     RECT  35.891 3.984 36.217 9 ;
     RECT  35.363 21.84 36.245 27.96 ;
     RECT  36.217 4.56 36.385 9 ;
     RECT  35.417 12.048 36.385 17.112 ;
     RECT  36.385 12.048 36.461 17.64 ;
     RECT  36.085 18.768 36.461 20.328 ;
     RECT  36.385 4.56 36.469 9.144 ;
     RECT  36.245 23.328 36.529 27.96 ;
     RECT  36.461 20.112 36.853 20.328 ;
     RECT  36.245 21.84 36.853 22.008 ;
     RECT  35.939 10.128 36.961 10.152 ;
     RECT  36.961 10.128 37.045 10.2 ;
     RECT  36.097 1.728 37.1 2.232 ;
     RECT  37.1 1.728 37.285 2.28 ;
     RECT  37.285 1.728 37.349 3.048 ;
     RECT  36.469 4.56 37.349 9 ;
     RECT  37.349 1.728 37.508 9 ;
     RECT  37.045 10.128 37.508 10.248 ;
     RECT  36.461 12.528 37.508 17.64 ;
     RECT  36.461 18.768 37.508 19.032 ;
     RECT  36.853 20.112 37.508 22.008 ;
     RECT  36.529 23.328 37.508 28.488 ;
     RECT  37.508 1.728 37.612 32.412 ;
     RECT  37.612 1.728 37.804 32.142 ;
     RECT  37.804 20.112 37.829 23.928 ;
     RECT  37.804 3.36 38.009 3.384 ;
     RECT  37.804 10.176 38.009 10.2 ;
     RECT  37.804 13.152 38.009 15.048 ;
     RECT  37.804 1.728 38.051 1.848 ;
     RECT  37.804 28.464 38.081 28.488 ;
     RECT  37.804 4.56 38.117 9 ;
     RECT  37.804 17.616 38.153 18.264 ;
     RECT  38.117 4.56 38.225 8.76 ;
     RECT  37.829 21.024 38.339 23.928 ;
     RECT  38.225 4.56 38.405 5.592 ;
     RECT  38.051 1.728 38.585 1.8 ;
     RECT  38.339 22.272 38.621 23.928 ;
     RECT  38.009 15.024 38.801 15.048 ;
     RECT  37.804 25.824 38.801 27.384 ;
     RECT  37.804 11.424 38.837 11.448 ;
     RECT  38.153 18.144 38.941 18.264 ;
     RECT  38.405 4.56 38.981 5.304 ;
     RECT  38.009 13.152 39.017 13.896 ;
     RECT  39.017 13.152 39.049 13.176 ;
     RECT  38.339 21.024 39.053 21.048 ;
     RECT  38.225 7.152 39.161 8.76 ;
     RECT  39.049 13.104 39.161 13.176 ;
     RECT  38.621 23.904 39.161 23.928 ;
     RECT  38.585 1.728 39.629 1.752 ;
     RECT  39.229 2.736 40.208 2.76 ;
     RECT  38.981 5.28 40.208 5.304 ;
     RECT  39.265 6.576 40.208 6.84 ;
     RECT  39.161 7.968 40.208 8.76 ;
     RECT  39.161 13.104 40.208 13.128 ;
     RECT  38.941 16.8 40.208 16.968 ;
     RECT  38.941 18.144 40.208 18.936 ;
     RECT  38.621 22.272 40.208 22.776 ;
     RECT  38.801 25.824 40.208 25.848 ;
     RECT  40.208 2.148 40.312 32.412 ;
     RECT  40.312 2.418 40.504 32.142 ;
     RECT  40.504 18.144 40.565 18.888 ;
     RECT  40.504 7.968 40.601 7.992 ;
     RECT  40.504 27.504 41.497 28.104 ;
     RECT  40.565 18.288 41.533 18.888 ;
     RECT  40.504 26.352 41.533 26.376 ;
     RECT  41.497 27.36 41.533 28.104 ;
     RECT  41.533 17.424 41.569 18.888 ;
     RECT  40.504 23.76 41.569 25.08 ;
     RECT  41.533 26.352 41.569 28.104 ;
     RECT  40.504 14.688 41.821 16.296 ;
     RECT  41.569 17.28 41.821 18.888 ;
     RECT  41.569 23.76 41.857 28.104 ;
     RECT  41.821 14.688 43.081 18.888 ;
     RECT  43.081 14.544 43.164 18.888 ;
     RECT  41.857 23.76 43.164 28.248 ;
    LAYER M5 ;
     RECT  9.936 0.016 28.248 0.037 ;
     RECT  5.328 0.016 6.648 0.131 ;
     RECT  9.936 0.037 28.344 0.275 ;
     RECT  9.936 0.275 28.104 0.611 ;
     RECT  10.08 0.611 28.104 0.659 ;
     RECT  10.08 0.659 18.168 1.187 ;
     RECT  12.528 1.187 18.168 1.235 ;
     RECT  10.08 1.187 11.112 1.763 ;
     RECT  12.96 1.235 18.168 1.763 ;
     RECT  29.52 0.016 38.616 1.763 ;
     RECT  5.472 0.131 6.648 1.811 ;
     RECT  10.224 1.763 11.112 1.811 ;
     RECT  29.52 1.763 38.472 1.811 ;
     RECT  29.52 1.811 38.04 1.859 ;
     RECT  10.224 1.811 10.824 2.051 ;
     RECT  5.472 1.811 6.072 2.137 ;
     RECT  13.2 1.763 18.168 2.137 ;
     RECT  19.152 0.659 28.104 2.137 ;
     RECT  29.52 1.859 32.52 2.137 ;
     RECT  2.4 2.137 2.52 2.151 ;
     RECT  7.8 2.137 7.92 2.151 ;
     RECT  40.2 2.137 40.32 2.151 ;
     RECT  33.696 1.859 37.812 2.243 ;
     RECT  5.1 2.137 6.072 2.291 ;
     RECT  10.224 2.051 10.812 2.291 ;
     RECT  13.2 2.137 28.104 2.291 ;
     RECT  37.152 2.243 37.812 2.291 ;
     RECT  10.368 2.291 10.812 2.339 ;
     RECT  29.4 2.137 32.52 2.915 ;
     RECT  13.2 2.291 13.656 2.963 ;
     RECT  37.296 2.291 37.812 3.059 ;
     RECT  15.744 2.291 28.104 3.107 ;
     RECT  33.696 2.243 36.168 3.155 ;
     RECT  34.8 3.155 36.168 3.251 ;
     RECT  7.8 2.151 8.112 3.397 ;
     RECT  15.744 3.107 27.528 3.443 ;
     RECT  10.5 2.339 10.812 3.541 ;
     RECT  5.1 2.291 5.412 3.589 ;
     RECT  29.4 2.915 29.712 3.733 ;
     RECT  4.56 3.589 5.412 3.877 ;
     RECT  33.696 3.155 33.72 3.923 ;
     RECT  36.144 3.251 36.168 4.019 ;
     RECT  31.248 2.915 32.52 4.163 ;
     RECT  13.2 2.963 13.512 4.165 ;
     RECT  7.8 3.397 8.664 4.403 ;
     RECT  29.184 3.733 29.712 4.501 ;
     RECT  4.56 3.877 5.64 4.547 ;
     RECT  37.392 3.059 37.812 4.549 ;
     RECT  31.248 4.163 32.412 4.595 ;
     RECT  15.9 3.443 27.528 4.645 ;
     RECT  29.088 4.501 30.168 4.645 ;
     RECT  10.5 3.541 11.352 4.693 ;
     RECT  15.9 4.645 30.168 4.835 ;
     RECT  29.088 4.835 30.168 4.979 ;
     RECT  13.104 4.165 13.512 5.123 ;
     RECT  29.28 4.979 30.168 5.171 ;
     RECT  31.872 4.595 32.412 5.173 ;
     RECT  10.5 4.693 11.4 5.269 ;
     RECT  36.816 4.549 37.812 5.269 ;
     RECT  31.872 5.173 32.76 5.315 ;
     RECT  15.9 4.835 27.528 5.459 ;
     RECT  31.872 5.315 32.412 5.459 ;
     RECT  36.816 5.269 37.992 5.507 ;
     RECT  37.056 5.507 37.992 5.555 ;
     RECT  15.9 5.459 19.032 5.747 ;
     RECT  13.2 5.123 13.512 6.085 ;
     RECT  29.28 5.171 29.928 6.179 ;
     RECT  34.8 3.251 35.112 6.181 ;
     RECT  15.9 5.747 17.016 6.229 ;
     RECT  20.736 5.459 27.528 6.229 ;
     RECT  15.552 6.229 17.016 6.323 ;
     RECT  10.5 5.269 11.688 6.373 ;
     RECT  29.28 6.179 29.88 6.709 ;
     RECT  32.1 5.459 32.412 6.709 ;
     RECT  10.5 6.373 12.12 6.805 ;
     RECT  31.968 6.709 32.412 6.805 ;
     RECT  20.736 6.229 27.912 6.851 ;
     RECT  34.8 6.181 35.832 6.851 ;
     RECT  29.232 6.709 29.88 6.853 ;
     RECT  20.736 6.851 24.312 6.899 ;
     RECT  25.68 6.851 27.912 6.899 ;
     RECT  15.552 6.323 16.392 6.947 ;
     RECT  25.68 6.899 27.48 7.043 ;
     RECT  9.648 6.805 12.12 7.189 ;
     RECT  13.2 6.085 13.656 7.189 ;
     RECT  25.728 7.043 27.48 7.235 ;
     RECT  18 5.747 19.032 7.237 ;
     RECT  29.088 6.853 29.88 7.331 ;
     RECT  15.552 6.947 16.212 7.333 ;
     RECT  18 7.237 19.224 7.333 ;
     RECT  6.768 5.077 6.792 7.381 ;
     RECT  7.8 4.403 8.112 7.381 ;
     RECT  9.648 7.189 13.656 7.427 ;
     RECT  20.736 6.899 22.488 7.475 ;
     RECT  29.184 7.331 29.88 7.523 ;
     RECT  25.728 7.235 27.012 7.571 ;
     RECT  18 7.333 19.56 7.715 ;
     RECT  29.184 7.523 29.712 7.811 ;
     RECT  31.872 6.805 32.412 7.907 ;
     RECT  34.8 6.851 35.112 7.909 ;
     RECT  37.056 5.555 37.812 7.909 ;
     RECT  21.3 7.475 22.488 8.003 ;
     RECT  21.3 8.003 22.056 8.147 ;
     RECT  9.648 7.427 10.812 8.291 ;
     RECT  12.24 7.427 13.656 8.579 ;
     RECT  13.2 8.579 13.656 8.915 ;
     RECT  31.92 7.907 32.412 8.915 ;
     RECT  5.1 4.547 5.64 8.917 ;
     RECT  6.768 7.381 8.112 8.917 ;
     RECT  18.6 7.715 19.56 9.011 ;
     RECT  24 6.899 24.312 9.013 ;
     RECT  15.12 7.333 16.212 9.155 ;
     RECT  30.72 8.245 30.744 9.155 ;
     RECT  36.432 7.909 37.812 9.155 ;
     RECT  26.16 7.571 27.012 9.349 ;
     RECT  34.8 7.909 35.208 9.349 ;
     RECT  23.568 9.013 24.312 9.587 ;
     RECT  29.4 7.811 29.712 9.685 ;
     RECT  34.8 9.349 35.352 9.779 ;
     RECT  25.536 9.349 27.012 9.923 ;
     RECT  5.1 8.917 8.112 9.971 ;
     RECT  37.296 9.155 37.812 10.117 ;
     RECT  7.392 9.971 8.112 10.165 ;
     RECT  7.392 10.165 8.424 10.211 ;
     RECT  37.056 10.117 37.812 10.259 ;
     RECT  32.1 8.915 32.412 10.453 ;
     RECT  33.6 8.869 33.624 10.453 ;
     RECT  32.1 10.453 33.624 10.499 ;
     RECT  34.8 9.779 35.112 10.789 ;
     RECT  29.04 9.685 29.712 10.835 ;
     RECT  7.8 10.211 8.424 10.883 ;
     RECT  32.1 10.499 33.336 11.459 ;
     RECT  32.1 11.459 32.412 11.701 ;
     RECT  29.4 10.835 29.712 12.325 ;
     RECT  28.896 12.325 29.712 12.373 ;
     RECT  26.208 9.923 27.012 12.469 ;
     RECT  25.68 12.469 27.012 12.515 ;
     RECT  13.2 8.915 13.608 12.565 ;
     RECT  19.968 10.165 19.992 12.803 ;
     RECT  13.2 12.565 14.52 12.851 ;
     RECT  5.1 9.971 6.312 13.045 ;
     RECT  7.8 10.883 8.112 13.045 ;
     RECT  13.2 12.851 13.608 13.045 ;
     RECT  5.1 13.045 8.112 13.091 ;
     RECT  31.344 11.701 32.412 13.139 ;
     RECT  37.248 10.259 37.812 13.141 ;
     RECT  6.864 13.091 8.112 13.331 ;
     RECT  24 9.587 24.312 13.381 ;
     RECT  25.68 12.515 25.704 13.427 ;
     RECT  23.904 13.381 24.312 13.571 ;
     RECT  13.008 13.045 13.608 13.619 ;
     RECT  37.104 13.141 37.812 13.715 ;
     RECT  28.896 12.373 30.168 14.147 ;
     RECT  0.144 14.389 0.168 14.531 ;
     RECT  10.5 8.291 10.812 14.677 ;
     RECT  13.008 13.619 13.512 14.725 ;
     RECT  21.3 8.147 21.612 14.773 ;
     RECT  24 13.571 24.312 14.773 ;
     RECT  10.5 14.677 11.4 14.869 ;
     RECT  12.528 14.725 13.512 14.869 ;
     RECT  34.8 10.789 35.928 15.349 ;
     RECT  34.8 15.349 36.12 15.395 ;
     RECT  37.248 13.715 37.812 15.443 ;
     RECT  28.896 14.147 29.712 15.445 ;
     RECT  28.8 15.445 29.712 15.635 ;
     RECT  5.1 13.091 5.64 15.877 ;
     RECT  24 14.773 24.936 15.925 ;
     RECT  7.344 13.331 8.112 16.019 ;
     RECT  10.5 14.869 13.512 16.019 ;
     RECT  4.56 15.877 5.64 16.069 ;
     RECT  4.56 16.069 6.504 16.115 ;
     RECT  21.3 14.773 21.72 16.403 ;
     RECT  23.568 15.925 24.936 16.403 ;
     RECT  4.56 16.115 5.412 16.595 ;
     RECT  7.8 16.019 8.112 17.365 ;
     RECT  17.184 17.125 17.208 17.603 ;
     RECT  5.1 16.595 5.412 17.605 ;
     RECT  24 16.403 24.936 17.605 ;
     RECT  7.8 17.365 9.096 17.653 ;
     RECT  26.7 12.515 27.012 18.181 ;
     RECT  4.752 17.605 5.412 18.563 ;
     RECT  34.8 15.395 35.112 18.757 ;
     RECT  36.096 15.395 36.12 18.757 ;
     RECT  34.8 18.757 36.12 18.949 ;
     RECT  32.1 13.139 32.412 19.333 ;
     RECT  34.8 18.949 36.264 19.523 ;
     RECT  6.48 16.115 6.504 20.005 ;
     RECT  2.4 2.151 2.712 20.101 ;
     RECT  28.944 15.635 29.712 20.195 ;
     RECT  7.68 17.653 9.096 20.339 ;
     RECT  26.7 18.181 27.24 20.339 ;
     RECT  34.8 19.523 36.216 20.339 ;
     RECT  31.344 19.333 32.412 20.627 ;
     RECT  2.4 20.101 2.808 20.677 ;
     RECT  10.5 16.019 10.812 20.725 ;
     RECT  24 17.605 25.224 20.771 ;
     RECT  37.5 15.443 37.812 21.013 ;
     RECT  2.256 20.677 2.808 21.059 ;
     RECT  19.968 19.909 19.992 21.107 ;
     RECT  29.28 20.195 29.712 21.251 ;
     RECT  6.48 20.005 6.648 21.445 ;
     RECT  7.8 20.339 9.096 21.445 ;
     RECT  21.3 16.403 21.612 21.445 ;
     RECT  6.48 21.445 9.096 21.491 ;
     RECT  21.12 21.445 21.612 21.587 ;
     RECT  24 20.771 25.128 21.637 ;
     RECT  12.288 16.019 13.512 21.683 ;
     RECT  29.4 21.251 29.712 22.021 ;
     RECT  13.2 21.683 13.512 22.741 ;
     RECT  37.5 21.013 38.328 22.787 ;
     RECT  26.7 20.339 27.012 22.789 ;
     RECT  10.224 20.725 10.812 22.931 ;
     RECT  29.4 22.021 30.264 22.979 ;
     RECT  23.808 21.637 25.128 23.029 ;
     RECT  26.7 22.789 27.96 23.029 ;
     RECT  23.808 23.029 27.96 23.315 ;
     RECT  12.528 22.741 13.512 23.555 ;
     RECT  24 23.315 27.96 23.605 ;
     RECT  32.1 20.627 32.412 23.653 ;
     RECT  24 23.605 28.056 23.891 ;
     RECT  15.9 9.155 16.212 23.893 ;
     RECT  33.744 22.741 33.768 23.939 ;
     RECT  10.5 22.931 10.812 24.469 ;
     RECT  36.192 20.339 36.216 24.469 ;
     RECT  31.872 23.653 32.412 24.563 ;
     RECT  24 23.891 27.96 24.659 ;
     RECT  6.624 21.491 9.096 25.045 ;
     RECT  15.9 23.893 16.536 25.045 ;
     RECT  24 24.659 27.012 25.091 ;
     RECT  36.192 24.469 36.408 25.139 ;
     RECT  10.5 24.469 11.4 25.237 ;
     RECT  6.528 25.045 9.096 25.429 ;
     RECT  10.224 25.237 11.4 25.429 ;
     RECT  6.528 25.429 11.4 25.475 ;
     RECT  15.792 25.045 16.536 25.667 ;
     RECT  36.192 25.139 36.264 25.667 ;
     RECT  7.8 25.475 11.4 25.715 ;
     RECT  7.8 25.715 10.92 25.763 ;
     RECT  29.4 22.979 29.712 26.149 ;
     RECT  32.1 24.563 32.412 26.149 ;
     RECT  24 25.091 25.512 26.291 ;
     RECT  10.5 25.763 10.92 26.819 ;
     RECT  29.4 26.149 29.832 26.819 ;
     RECT  33.6 25.189 33.624 26.819 ;
     RECT  13.2 23.555 13.512 27.205 ;
     RECT  31.632 26.149 32.412 27.251 ;
     RECT  6.528 25.475 6.552 27.301 ;
     RECT  7.8 25.763 9.096 27.301 ;
     RECT  12.48 27.205 13.512 27.301 ;
     RECT  3.792 26.773 3.816 27.347 ;
     RECT  34.8 20.339 35.208 27.397 ;
     RECT  36.192 25.667 36.216 27.397 ;
     RECT  5.1 18.563 5.412 27.781 ;
     RECT  6.528 27.301 9.096 27.877 ;
     RECT  10.5 26.819 10.812 27.877 ;
     RECT  37.5 22.787 37.812 27.877 ;
     RECT  34.8 27.397 36.216 27.971 ;
     RECT  6.528 27.877 9.336 28.403 ;
     RECT  7.8 28.403 9.336 28.405 ;
     RECT  10.368 27.877 10.812 28.405 ;
     RECT  37.392 27.877 37.812 28.499 ;
     RECT  34.8 27.971 35.352 28.547 ;
     RECT  12.48 27.301 14.232 28.645 ;
     RECT  7.8 28.405 10.812 28.739 ;
     RECT  15.9 25.667 16.536 28.787 ;
     RECT  7.8 28.739 9.336 28.979 ;
     RECT  12.336 28.645 14.232 28.979 ;
     RECT  18.6 9.011 18.912 28.981 ;
     RECT  4.128 27.781 5.412 29.075 ;
     RECT  34.8 28.547 35.304 29.075 ;
     RECT  10.5 28.739 10.812 29.125 ;
     RECT  32.1 27.251 32.412 29.269 ;
     RECT  33.648 28.453 33.672 29.269 ;
     RECT  32.1 29.269 33.672 29.315 ;
     RECT  24 26.291 25.128 29.365 ;
     RECT  10.5 29.125 10.968 29.461 ;
     RECT  4.848 29.075 5.412 29.605 ;
     RECT  6.528 28.403 6.6 29.605 ;
     RECT  10.5 29.461 11.304 29.605 ;
     RECT  12.336 28.979 13.848 29.605 ;
     RECT  7.8 28.979 9.096 29.749 ;
     RECT  4.848 29.605 6.6 29.795 ;
     RECT  10.5 29.605 13.848 29.843 ;
     RECT  34.8 29.075 35.256 29.893 ;
     RECT  18.48 28.981 18.912 30.035 ;
     RECT  34.176 29.893 35.256 30.083 ;
     RECT  10.5 29.843 13.512 30.275 ;
     RECT  28.272 28.789 28.296 30.275 ;
     RECT  32.1 29.315 32.712 30.419 ;
     RECT  7.632 29.749 9.096 30.565 ;
     RECT  4.848 29.795 5.688 30.611 ;
     RECT  11.952 30.275 13.512 30.611 ;
     RECT  24 29.365 25.416 30.611 ;
     RECT  15.9 28.787 16.212 30.661 ;
     RECT  7.44 30.565 9.096 30.755 ;
     RECT  7.536 30.755 9.096 30.947 ;
     RECT  30.768 29.605 30.792 31.045 ;
     RECT  32.1 30.419 32.412 31.045 ;
     RECT  30.768 31.045 32.412 31.091 ;
     RECT  20.304 30.469 20.328 31.379 ;
     RECT  34.176 30.083 35.112 31.379 ;
     RECT  24 30.611 25.128 31.427 ;
     RECT  15.072 30.661 16.212 31.667 ;
     RECT  7.68 30.947 9.096 31.909 ;
     RECT  10.5 30.275 10.812 31.909 ;
     RECT  12.384 30.611 13.512 31.909 ;
     RECT  31.296 31.091 32.412 31.955 ;
     RECT  6.912 31.909 9.24 32.005 ;
     RECT  10.368 31.909 13.512 32.005 ;
     RECT  5.1 30.611 5.688 32.293 ;
     RECT  6.768 32.005 13.512 32.293 ;
     RECT  2.4 21.059 2.712 32.409 ;
     RECT  15.9 31.667 16.212 32.409 ;
     RECT  18.6 30.035 18.912 32.409 ;
     RECT  21.3 21.587 21.612 32.409 ;
     RECT  24 31.427 24.312 32.409 ;
     RECT  26.7 25.091 27.012 32.409 ;
     RECT  29.4 26.819 29.712 32.409 ;
     RECT  32.1 31.955 32.412 32.409 ;
     RECT  34.8 31.379 35.112 32.409 ;
     RECT  37.5 28.499 37.812 32.409 ;
     RECT  40.2 2.151 40.512 32.409 ;
     RECT  2.4 32.409 2.52 32.423 ;
     RECT  15.9 32.409 16.02 32.423 ;
     RECT  18.6 32.409 18.72 32.423 ;
     RECT  21.3 32.409 21.42 32.423 ;
     RECT  24 32.409 24.12 32.423 ;
     RECT  26.7 32.409 26.82 32.423 ;
     RECT  29.4 32.409 29.52 32.423 ;
     RECT  32.1 32.409 32.22 32.423 ;
     RECT  34.8 32.409 34.92 32.423 ;
     RECT  37.5 32.409 37.62 32.423 ;
     RECT  40.2 32.409 40.32 32.423 ;
     RECT  5.1 32.293 13.512 32.437 ;
     RECT  4.896 32.437 13.656 34.451 ;
     RECT  4.896 34.451 13.56 34.512 ;
  END
END qkd_seq_core_static_s
END LIBRARY
